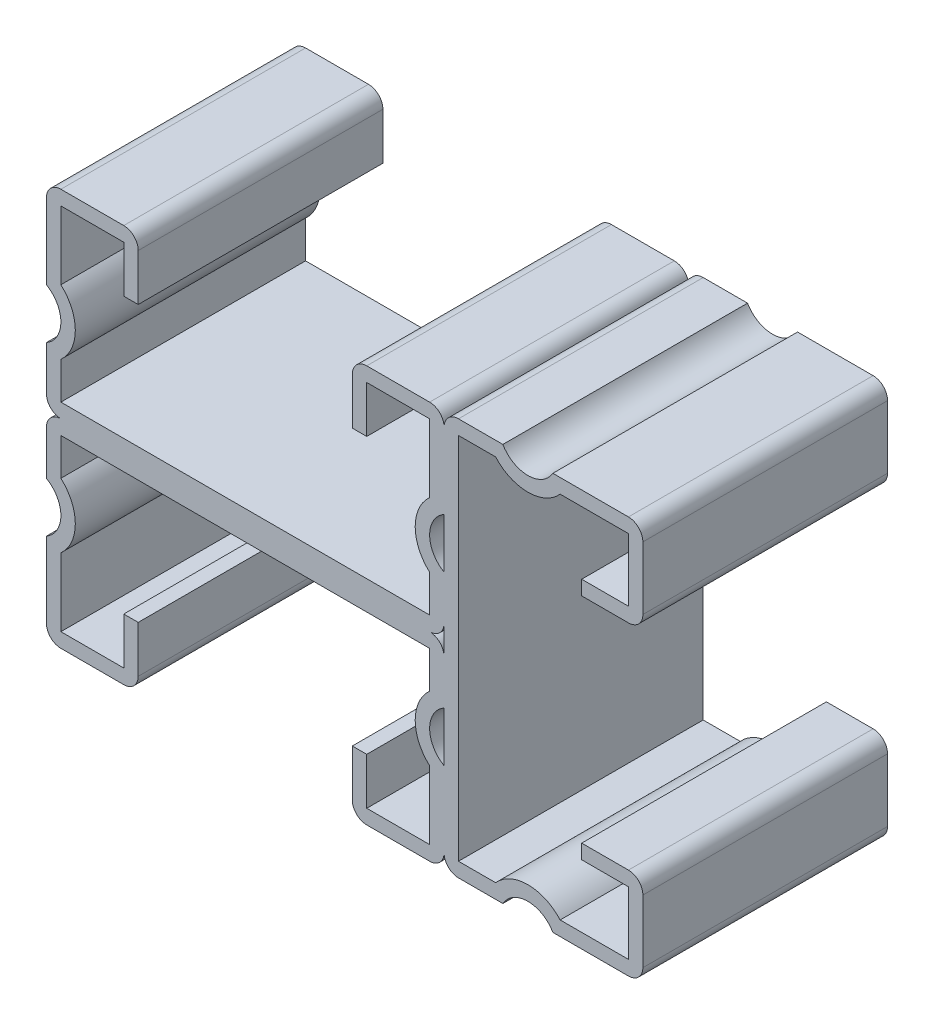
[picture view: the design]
ISO-10303-21;
HEADER;
FILE_DESCRIPTION(('STEP AP214'),'2;1');
FILE_NAME('part.step','',(''),(''),'','','');
FILE_SCHEMA(('AUTOMOTIVE_DESIGN { 1 0 10303 214 1 1 1 1 }'));
ENDSEC;
DATA;
#1=APPLICATION_CONTEXT('core data for automotive mechanical design processes');
#2=APPLICATION_PROTOCOL_DEFINITION('international standard','automotive_design',2000,#1);
#3=PRODUCT_CONTEXT('',#1,'mechanical');
#4=PRODUCT('Part','Part','',(#3));
#5=PRODUCT_RELATED_PRODUCT_CATEGORY('part','',(#4));
#6=PRODUCT_DEFINITION_FORMATION('','',#4);
#7=PRODUCT_DEFINITION_CONTEXT('part definition',#1,'design');
#8=PRODUCT_DEFINITION('design','',#6,#7);
#9=PRODUCT_DEFINITION_SHAPE('','',#8);
#10=(LENGTH_UNIT() NAMED_UNIT(*) SI_UNIT(.MILLI.,.METRE.));
#11=(NAMED_UNIT(*) PLANE_ANGLE_UNIT() SI_UNIT($,.RADIAN.));
#12=(NAMED_UNIT(*) SI_UNIT($,.STERADIAN.) SOLID_ANGLE_UNIT());
#13=UNCERTAINTY_MEASURE_WITH_UNIT(LENGTH_MEASURE(1.E-05),#10,'distance_accuracy_value','');
#14=(GEOMETRIC_REPRESENTATION_CONTEXT(3) GLOBAL_UNCERTAINTY_ASSIGNED_CONTEXT((#13)) GLOBAL_UNIT_ASSIGNED_CONTEXT((#10,
#11,#12)) REPRESENTATION_CONTEXT('',''));
#15=CARTESIAN_POINT('',(0.,0.,0.));
#16=DIRECTION('',(0.,0.,1.));
#17=DIRECTION('',(1.,0.,0.));
#18=AXIS2_PLACEMENT_3D('',#15,#16,#17);
#19=CARTESIAN_POINT('',(-19.1389,19.1389,12.7));
#20=DIRECTION('',(-1.,0.,0.));
#21=DIRECTION('',(0.,0.,1.));
#22=AXIS2_PLACEMENT_3D('',#19,#20,#21);
#23=PLANE('',#22);
#24=DIRECTION('',(0.,1.,0.));
#25=VECTOR('',#24,1.);
#26=CARTESIAN_POINT('',(-19.1389,19.1389,-12.7));
#27=LINE('',#26,#25);
#28=CARTESIAN_POINT('',(-19.1389,12.0504714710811,-12.7));
#29=VERTEX_POINT('',#28);
#30=CARTESIAN_POINT('',(-19.1389,19.1389,-12.7));
#31=VERTEX_POINT('',#30);
#32=EDGE_CURVE('E264',#29,#31,#27,.T.);
#33=ORIENTED_EDGE('',*,*,#32,.T.);
#34=DIRECTION('',(0.,0.,-1.));
#35=VECTOR('',#34,1.);
#36=CARTESIAN_POINT('',(-19.1389,19.1389,12.7));
#37=LINE('',#36,#35);
#38=CARTESIAN_POINT('',(-19.1389,19.1389,12.7));
#39=VERTEX_POINT('',#38);
#40=EDGE_CURVE('E11',#39,#31,#37,.T.);
#41=ORIENTED_EDGE('',*,*,#40,.F.);
#42=DIRECTION('',(0.,1.,0.));
#43=VECTOR('',#42,1.);
#44=CARTESIAN_POINT('',(-19.1389,19.1389,12.7));
#45=LINE('',#44,#43);
#46=CARTESIAN_POINT('',(-19.1389,12.0504714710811,12.7));
#47=VERTEX_POINT('',#46);
#48=EDGE_CURVE('E317',#47,#39,#45,.T.);
#49=ORIENTED_EDGE('',*,*,#48,.F.);
#50=DIRECTION('',(0.,0.,-1.));
#51=VECTOR('',#50,1.);
#52=CARTESIAN_POINT('',(-19.1389,12.0504714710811,12.7));
#53=LINE('',#52,#51);
#54=EDGE_CURVE('E260',#47,#29,#53,.T.);
#55=ORIENTED_EDGE('',*,*,#54,.T.);
#56=EDGE_LOOP('',(#33,#41,#49,#55));
#57=FACE_BOUND('',#56,.T.);
#58=ADVANCED_FACE('F39',(#57),#23,.F.);
#59=CARTESIAN_POINT('',(-19.1389,19.1389,12.7));
#60=DIRECTION('',(0.,1.,0.));
#61=DIRECTION('',(0.,0.,1.));
#62=AXIS2_PLACEMENT_3D('',#59,#60,#61);
#63=PLANE('',#62);
#64=DIRECTION('',(1.,0.,0.));
#65=VECTOR('',#64,1.);
#66=CARTESIAN_POINT('',(-19.1389,19.1389,-12.7));
#67=LINE('',#66,#65);
#68=CARTESIAN_POINT('',(-12.6111,19.1389,-12.7));
#69=VERTEX_POINT('',#68);
#70=EDGE_CURVE('E267',#31,#69,#67,.T.);
#71=ORIENTED_EDGE('',*,*,#70,.T.);
#72=DIRECTION('',(0.,0.,-1.));
#73=VECTOR('',#72,1.);
#74=CARTESIAN_POINT('',(-12.6111,19.1389,12.7));
#75=LINE('',#74,#73);
#76=CARTESIAN_POINT('',(-12.6111,19.1389,12.7));
#77=VERTEX_POINT('',#76);
#78=EDGE_CURVE('E47',#77,#69,#75,.T.);
#79=ORIENTED_EDGE('',*,*,#78,.F.);
#80=DIRECTION('',(1.,0.,0.));
#81=VECTOR('',#80,1.);
#82=CARTESIAN_POINT('',(-19.1389,19.1389,12.7));
#83=LINE('',#82,#81);
#84=EDGE_CURVE('E156',#39,#77,#83,.T.);
#85=ORIENTED_EDGE('',*,*,#84,.F.);
#86=ORIENTED_EDGE('',*,*,#40,.T.);
#87=EDGE_LOOP('',(#71,#79,#85,#86));
#88=FACE_BOUND('',#87,.T.);
#89=ADVANCED_FACE('F483',(#88),#63,.F.);
#90=CARTESIAN_POINT('',(-12.6111,19.1389,12.7));
#91=DIRECTION('',(1.,0.,0.));
#92=DIRECTION('',(0.,1.,0.));
#93=AXIS2_PLACEMENT_3D('',#90,#91,#92);
#94=PLANE('',#93);
#95=DIRECTION('',(0.,-1.,0.));
#96=VECTOR('',#95,1.);
#97=CARTESIAN_POINT('',(-12.6111,19.1389,-12.7));
#98=LINE('',#97,#96);
#99=CARTESIAN_POINT('',(-12.6111,14.2875,-12.7));
#100=VERTEX_POINT('',#99);
#101=EDGE_CURVE('E270',#69,#100,#98,.T.);
#102=ORIENTED_EDGE('',*,*,#101,.T.);
#103=DIRECTION('',(0.,0.,-1.));
#104=VECTOR('',#103,1.);
#105=CARTESIAN_POINT('',(-12.6111,14.2875,12.7));
#106=LINE('',#105,#104);
#107=CARTESIAN_POINT('',(-12.6111,14.2875,12.7));
#108=VERTEX_POINT('',#107);
#109=EDGE_CURVE('E390',#108,#100,#106,.T.);
#110=ORIENTED_EDGE('',*,*,#109,.F.);
#111=DIRECTION('',(0.,-1.,0.));
#112=VECTOR('',#111,1.);
#113=CARTESIAN_POINT('',(-12.6111,19.1389,12.7));
#114=LINE('',#113,#112);
#115=EDGE_CURVE('E398',#77,#108,#114,.T.);
#116=ORIENTED_EDGE('',*,*,#115,.F.);
#117=ORIENTED_EDGE('',*,*,#78,.T.);
#118=EDGE_LOOP('',(#102,#110,#116,#117));
#119=FACE_BOUND('',#118,.T.);
#120=ADVANCED_FACE('F396',(#119),#94,.F.);
#121=CARTESIAN_POINT('',(-12.6111,14.2875,12.7));
#122=DIRECTION('',(0.,1.,0.));
#123=DIRECTION('',(0.,0.,1.));
#124=AXIS2_PLACEMENT_3D('',#121,#122,#123);
#125=PLANE('',#124);
#126=DIRECTION('',(1.,0.,0.));
#127=VECTOR('',#126,1.);
#128=CARTESIAN_POINT('',(-12.6111,14.2875,-12.7));
#129=LINE('',#128,#127);
#130=CARTESIAN_POINT('',(-11.1125,14.2875,-12.7));
#131=VERTEX_POINT('',#130);
#132=EDGE_CURVE('E272',#100,#131,#129,.T.);
#133=ORIENTED_EDGE('',*,*,#132,.T.);
#134=DIRECTION('',(0.,0.,-1.));
#135=VECTOR('',#134,1.);
#136=CARTESIAN_POINT('',(-11.1125,14.2875,12.7));
#137=LINE('',#136,#135);
#138=CARTESIAN_POINT('',(-11.1125,14.2875,12.7));
#139=VERTEX_POINT('',#138);
#140=EDGE_CURVE('E387',#139,#131,#137,.T.);
#141=ORIENTED_EDGE('',*,*,#140,.F.);
#142=DIRECTION('',(1.,0.,0.));
#143=VECTOR('',#142,1.);
#144=CARTESIAN_POINT('',(-12.6111,14.2875,12.7));
#145=LINE('',#144,#143);
#146=EDGE_CURVE('E418',#108,#139,#145,.T.);
#147=ORIENTED_EDGE('',*,*,#146,.F.);
#148=ORIENTED_EDGE('',*,*,#109,.T.);
#149=EDGE_LOOP('',(#133,#141,#147,#148));
#150=FACE_BOUND('',#149,.T.);
#151=ADVANCED_FACE('F409',(#150),#125,.F.);
#152=CARTESIAN_POINT('',(-11.1125,19.1389,12.7));
#153=DIRECTION('',(-1.,0.,0.));
#154=DIRECTION('',(0.,-1.,0.));
#155=AXIS2_PLACEMENT_3D('',#152,#153,#154);
#156=PLANE('',#155);
#157=DIRECTION('',(0.,1.,0.));
#158=VECTOR('',#157,1.);
#159=CARTESIAN_POINT('',(-11.1125,19.1389,-12.7));
#160=LINE('',#159,#158);
#161=CARTESIAN_POINT('',(-11.1125,19.1389,-12.7));
#162=VERTEX_POINT('',#161);
#163=EDGE_CURVE('E274',#131,#162,#160,.T.);
#164=ORIENTED_EDGE('',*,*,#163,.T.);
#165=DIRECTION('',(0.,0.,-1.));
#166=VECTOR('',#165,1.);
#167=CARTESIAN_POINT('',(-11.1125,19.1389,12.7));
#168=LINE('',#167,#166);
#169=CARTESIAN_POINT('',(-11.1125,19.1389,12.7));
#170=VERTEX_POINT('',#169);
#171=EDGE_CURVE('E384',#170,#162,#168,.T.);
#172=ORIENTED_EDGE('',*,*,#171,.F.);
#173=DIRECTION('',(0.,1.,0.));
#174=VECTOR('',#173,1.);
#175=CARTESIAN_POINT('',(-11.1125,19.1389,12.7));
#176=LINE('',#175,#174);
#177=EDGE_CURVE('E415',#139,#170,#176,.T.);
#178=ORIENTED_EDGE('',*,*,#177,.F.);
#179=ORIENTED_EDGE('',*,*,#140,.T.);
#180=EDGE_LOOP('',(#164,#172,#178,#179));
#181=FACE_BOUND('',#180,.T.);
#182=ADVANCED_FACE('F413',(#181),#156,.F.);
#183=CARTESIAN_POINT('',(-12.6111,19.1389,12.7));
#184=DIRECTION('',(0.,0.,-1.));
#185=DIRECTION('',(-1.,0.,0.));
#186=AXIS2_PLACEMENT_3D('',#183,#184,#185);
#187=CYLINDRICAL_SURFACE('',#186,1.4986);
#188=CARTESIAN_POINT('',(-12.6111,19.1389,-12.7));
#189=DIRECTION('',(0.,0.,1.));
#190=DIRECTION('',(-1.,0.,0.));
#191=AXIS2_PLACEMENT_3D('',#188,#189,#190);
#192=CIRCLE('',#191,1.4986);
#193=CARTESIAN_POINT('',(-12.6111,20.6375,-12.7));
#194=VERTEX_POINT('',#193);
#195=EDGE_CURVE('E276',#162,#194,#192,.T.);
#196=ORIENTED_EDGE('',*,*,#195,.T.);
#197=DIRECTION('',(0.,0.,-1.));
#198=VECTOR('',#197,1.);
#199=CARTESIAN_POINT('',(-12.6111,20.6375,12.7));
#200=LINE('',#199,#198);
#201=CARTESIAN_POINT('',(-12.6111,20.6375,12.7));
#202=VERTEX_POINT('',#201);
#203=EDGE_CURVE('E381',#202,#194,#200,.T.);
#204=ORIENTED_EDGE('',*,*,#203,.F.);
#205=CARTESIAN_POINT('',(-12.6111,19.1389,12.7));
#206=DIRECTION('',(0.,0.,1.));
#207=DIRECTION('',(-1.,0.,0.));
#208=AXIS2_PLACEMENT_3D('',#205,#206,#207);
#209=CIRCLE('',#208,1.4986);
#210=EDGE_CURVE('E417',#170,#202,#209,.T.);
#211=ORIENTED_EDGE('',*,*,#210,.F.);
#212=ORIENTED_EDGE('',*,*,#171,.T.);
#213=EDGE_LOOP('',(#196,#204,#211,#212));
#214=FACE_BOUND('',#213,.T.);
#215=ADVANCED_FACE('F496',(#214),#187,.T.);
#216=CARTESIAN_POINT('',(-19.1389,20.6375,12.7));
#217=DIRECTION('',(0.,-1.,0.));
#218=DIRECTION('',(0.,0.,-1.));
#219=AXIS2_PLACEMENT_3D('',#216,#217,#218);
#220=PLANE('',#219);
#221=DIRECTION('',(-1.,0.,0.));
#222=VECTOR('',#221,1.);
#223=CARTESIAN_POINT('',(-19.1389,20.6375,-12.7));
#224=LINE('',#223,#222);
#225=CARTESIAN_POINT('',(-19.1389,20.6375,-12.7));
#226=VERTEX_POINT('',#225);
#227=EDGE_CURVE('E278',#194,#226,#224,.T.);
#228=ORIENTED_EDGE('',*,*,#227,.T.);
#229=DIRECTION('',(0.,0.,-1.));
#230=VECTOR('',#229,1.);
#231=CARTESIAN_POINT('',(-19.1389,20.6375,12.7));
#232=LINE('',#231,#230);
#233=CARTESIAN_POINT('',(-19.1389,20.6375,12.7));
#234=VERTEX_POINT('',#233);
#235=EDGE_CURVE('E378',#234,#226,#232,.T.);
#236=ORIENTED_EDGE('',*,*,#235,.F.);
#237=DIRECTION('',(-1.,0.,0.));
#238=VECTOR('',#237,1.);
#239=CARTESIAN_POINT('',(-19.1389,20.6375,12.7));
#240=LINE('',#239,#238);
#241=EDGE_CURVE('E420',#202,#234,#240,.T.);
#242=ORIENTED_EDGE('',*,*,#241,.F.);
#243=ORIENTED_EDGE('',*,*,#203,.T.);
#244=EDGE_LOOP('',(#228,#236,#242,#243));
#245=FACE_BOUND('',#244,.T.);
#246=ADVANCED_FACE('F499',(#245),#220,.F.);
#247=CARTESIAN_POINT('',(-19.1389,19.1389,12.7));
#248=DIRECTION('',(0.,0.,-1.));
#249=DIRECTION('',(-1.,0.,0.));
#250=AXIS2_PLACEMENT_3D('',#247,#248,#249);
#251=CYLINDRICAL_SURFACE('',#250,1.4986);
#252=CARTESIAN_POINT('',(-19.1389,19.1389,-12.7));
#253=DIRECTION('',(0.,0.,1.));
#254=DIRECTION('',(-1.,0.,0.));
#255=AXIS2_PLACEMENT_3D('',#252,#253,#254);
#256=CIRCLE('',#255,1.4986);
#257=CARTESIAN_POINT('',(-20.6375,19.1389,-12.7));
#258=VERTEX_POINT('',#257);
#259=EDGE_CURVE('E280',#226,#258,#256,.T.);
#260=ORIENTED_EDGE('',*,*,#259,.T.);
#261=DIRECTION('',(0.,0.,-1.));
#262=VECTOR('',#261,1.);
#263=CARTESIAN_POINT('',(-20.6375,19.1389,12.7));
#264=LINE('',#263,#262);
#265=CARTESIAN_POINT('',(-20.6375,19.1389,12.7));
#266=VERTEX_POINT('',#265);
#267=EDGE_CURVE('E375',#266,#258,#264,.T.);
#268=ORIENTED_EDGE('',*,*,#267,.F.);
#269=CARTESIAN_POINT('',(-19.1389,19.1389,12.7));
#270=DIRECTION('',(0.,0.,1.));
#271=DIRECTION('',(-1.,0.,0.));
#272=AXIS2_PLACEMENT_3D('',#269,#270,#271);
#273=CIRCLE('',#272,1.4986);
#274=EDGE_CURVE('E426',#234,#266,#273,.T.);
#275=ORIENTED_EDGE('',*,*,#274,.F.);
#276=ORIENTED_EDGE('',*,*,#235,.T.);
#277=EDGE_LOOP('',(#260,#268,#275,#276));
#278=FACE_BOUND('',#277,.T.);
#279=ADVANCED_FACE('F503',(#278),#251,.T.);
#280=CARTESIAN_POINT('',(-20.6375,19.1389,12.7));
#281=DIRECTION('',(1.,0.,0.));
#282=DIRECTION('',(0.,1.,0.));
#283=AXIS2_PLACEMENT_3D('',#280,#281,#282);
#284=PLANE('',#283);
#285=DIRECTION('',(0.,-1.,0.));
#286=VECTOR('',#285,1.);
#287=CARTESIAN_POINT('',(-20.6375,19.1389,-12.7));
#288=LINE('',#287,#286);
#289=CARTESIAN_POINT('',(-20.6375,11.2951513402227,-12.7));
#290=VERTEX_POINT('',#289);
#291=EDGE_CURVE('E282',#258,#290,#288,.T.);
#292=ORIENTED_EDGE('',*,*,#291,.T.);
#293=DIRECTION('',(0.,0.,-1.));
#294=VECTOR('',#293,1.);
#295=CARTESIAN_POINT('',(-20.6375,11.2951513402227,12.7));
#296=LINE('',#295,#294);
#297=CARTESIAN_POINT('',(-20.6375,11.2951513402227,12.7));
#298=VERTEX_POINT('',#297);
#299=EDGE_CURVE('E372',#298,#290,#296,.T.);
#300=ORIENTED_EDGE('',*,*,#299,.F.);
#301=DIRECTION('',(0.,-1.,0.));
#302=VECTOR('',#301,1.);
#303=CARTESIAN_POINT('',(-20.6375,19.1389,12.7));
#304=LINE('',#303,#302);
#305=EDGE_CURVE('E428',#266,#298,#304,.T.);
#306=ORIENTED_EDGE('',*,*,#305,.F.);
#307=ORIENTED_EDGE('',*,*,#267,.T.);
#308=EDGE_LOOP('',(#292,#300,#306,#307));
#309=FACE_BOUND('',#308,.T.);
#310=ADVANCED_FACE('F507',(#309),#284,.F.);
#311=CARTESIAN_POINT('',(-22.1361,8.69949999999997,12.7));
#312=DIRECTION('',(0.,0.,-1.));
#313=DIRECTION('',(-1.,0.,0.));
#314=AXIS2_PLACEMENT_3D('',#311,#312,#313);
#315=CYLINDRICAL_SURFACE('',#314,2.9972);
#316=CARTESIAN_POINT('',(-22.1361,8.69949999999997,-12.7));
#317=DIRECTION('',(0.,0.,-1.));
#318=DIRECTION('',(1.,0.,0.));
#319=AXIS2_PLACEMENT_3D('',#316,#317,#318);
#320=CIRCLE('',#319,2.9972);
#321=CARTESIAN_POINT('',(-20.6375,6.10384865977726,-12.7));
#322=VERTEX_POINT('',#321);
#323=EDGE_CURVE('E284',#290,#322,#320,.T.);
#324=ORIENTED_EDGE('',*,*,#323,.T.);
#325=DIRECTION('',(0.,0.,-1.));
#326=VECTOR('',#325,1.);
#327=CARTESIAN_POINT('',(-20.6375,6.10384865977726,12.7));
#328=LINE('',#327,#326);
#329=CARTESIAN_POINT('',(-20.6375,6.10384865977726,12.7));
#330=VERTEX_POINT('',#329);
#331=EDGE_CURVE('E369',#330,#322,#328,.T.);
#332=ORIENTED_EDGE('',*,*,#331,.F.);
#333=CARTESIAN_POINT('',(-22.1361,8.69949999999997,12.7));
#334=DIRECTION('',(0.,0.,-1.));
#335=DIRECTION('',(1.,0.,0.));
#336=AXIS2_PLACEMENT_3D('',#333,#334,#335);
#337=CIRCLE('',#336,2.9972);
#338=EDGE_CURVE('E430',#298,#330,#337,.T.);
#339=ORIENTED_EDGE('',*,*,#338,.F.);
#340=ORIENTED_EDGE('',*,*,#299,.T.);
#341=EDGE_LOOP('',(#324,#332,#339,#340));
#342=FACE_BOUND('',#341,.T.);
#343=ADVANCED_FACE('F511',(#342),#315,.F.);
#344=CARTESIAN_POINT('',(-20.6375,6.10384865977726,12.7));
#345=DIRECTION('',(1.,0.,0.));
#346=DIRECTION('',(0.,0.,-1.));
#347=AXIS2_PLACEMENT_3D('',#344,#345,#346);
#348=PLANE('',#347);
#349=DIRECTION('',(0.,-1.,0.));
#350=VECTOR('',#349,1.);
#351=CARTESIAN_POINT('',(-20.6375,6.10384865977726,-12.7));
#352=LINE('',#351,#350);
#353=CARTESIAN_POINT('',(-20.6375,1.4986,-12.7));
#354=VERTEX_POINT('',#353);
#355=EDGE_CURVE('E286',#322,#354,#352,.T.);
#356=ORIENTED_EDGE('',*,*,#355,.T.);
#357=DIRECTION('',(0.,0.,-1.));
#358=VECTOR('',#357,1.);
#359=CARTESIAN_POINT('',(-20.6375,1.4986,12.7));
#360=LINE('',#359,#358);
#361=CARTESIAN_POINT('',(-20.6375,1.4986,12.7));
#362=VERTEX_POINT('',#361);
#363=EDGE_CURVE('E366',#362,#354,#360,.T.);
#364=ORIENTED_EDGE('',*,*,#363,.F.);
#365=DIRECTION('',(0.,-1.,0.));
#366=VECTOR('',#365,1.);
#367=CARTESIAN_POINT('',(-20.6375,6.10384865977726,12.7));
#368=LINE('',#367,#366);
#369=EDGE_CURVE('E432',#330,#362,#368,.T.);
#370=ORIENTED_EDGE('',*,*,#369,.F.);
#371=ORIENTED_EDGE('',*,*,#331,.T.);
#372=EDGE_LOOP('',(#356,#364,#370,#371));
#373=FACE_BOUND('',#372,.T.);
#374=ADVANCED_FACE('F515',(#373),#348,.F.);
#375=CARTESIAN_POINT('',(-19.1389,1.4986,12.7));
#376=DIRECTION('',(0.,0.,-1.));
#377=DIRECTION('',(-1.,0.,0.));
#378=AXIS2_PLACEMENT_3D('',#375,#376,#377);
#379=CYLINDRICAL_SURFACE('',#378,1.4986);
#380=CARTESIAN_POINT('',(-19.1389,1.4986,-12.7));
#381=DIRECTION('',(0.,0.,1.));
#382=DIRECTION('',(-1.,0.,0.));
#383=AXIS2_PLACEMENT_3D('',#380,#381,#382);
#384=CIRCLE('',#383,1.4986);
#385=CARTESIAN_POINT('',(-19.1389,0.,-12.7));
#386=VERTEX_POINT('',#385);
#387=EDGE_CURVE('E288',#354,#386,#384,.T.);
#388=ORIENTED_EDGE('',*,*,#387,.T.);
#389=DIRECTION('',(0.,0.,-1.));
#390=VECTOR('',#389,1.);
#391=CARTESIAN_POINT('',(-19.1389,0.,12.7));
#392=LINE('',#391,#390);
#393=CARTESIAN_POINT('',(-19.1389,0.,12.7));
#394=VERTEX_POINT('',#393);
#395=EDGE_CURVE('E363',#394,#386,#392,.T.);
#396=ORIENTED_EDGE('',*,*,#395,.F.);
#397=CARTESIAN_POINT('',(-19.1389,1.4986,12.7));
#398=DIRECTION('',(0.,0.,1.));
#399=DIRECTION('',(-1.,0.,0.));
#400=AXIS2_PLACEMENT_3D('',#397,#398,#399);
#401=CIRCLE('',#400,1.4986);
#402=EDGE_CURVE('E434',#362,#394,#401,.T.);
#403=ORIENTED_EDGE('',*,*,#402,.F.);
#404=ORIENTED_EDGE('',*,*,#363,.T.);
#405=EDGE_LOOP('',(#388,#396,#403,#404));
#406=FACE_BOUND('',#405,.T.);
#407=ADVANCED_FACE('F519',(#406),#379,.T.);
#408=CARTESIAN_POINT('',(19.1389,1.49860000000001,12.7));
#409=DIRECTION('',(0.,0.,-1.));
#410=DIRECTION('',(-1.,0.,0.));
#411=AXIS2_PLACEMENT_3D('',#408,#409,#410);
#412=CYLINDRICAL_SURFACE('',#411,1.4986);
#413=CARTESIAN_POINT('',(19.1389,1.49860000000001,-12.7));
#414=DIRECTION('',(0.,0.,1.));
#415=DIRECTION('',(-1.,0.,0.));
#416=AXIS2_PLACEMENT_3D('',#413,#414,#415);
#417=CIRCLE('',#416,1.4986);
#418=CARTESIAN_POINT('',(19.1389,0.,-12.7));
#419=VERTEX_POINT('',#418);
#420=CARTESIAN_POINT('',(20.6375,1.49860000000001,-12.7));
#421=VERTEX_POINT('',#420);
#422=EDGE_CURVE('E290',#419,#421,#417,.T.);
#423=ORIENTED_EDGE('',*,*,#422,.T.);
#424=DIRECTION('',(0.,0.,-1.));
#425=VECTOR('',#424,1.);
#426=CARTESIAN_POINT('',(20.6375,1.49860000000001,12.7));
#427=LINE('',#426,#425);
#428=CARTESIAN_POINT('',(20.6375,1.49860000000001,12.7));
#429=VERTEX_POINT('',#428);
#430=EDGE_CURVE('E357',#429,#421,#427,.T.);
#431=ORIENTED_EDGE('',*,*,#430,.F.);
#432=CARTESIAN_POINT('',(19.1389,1.49860000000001,12.7));
#433=DIRECTION('',(0.,0.,1.));
#434=DIRECTION('',(-1.,0.,0.));
#435=AXIS2_PLACEMENT_3D('',#432,#433,#434);
#436=CIRCLE('',#435,1.4986);
#437=CARTESIAN_POINT('',(19.1389,0.,12.7));
#438=VERTEX_POINT('',#437);
#439=EDGE_CURVE('E436',#438,#429,#436,.T.);
#440=ORIENTED_EDGE('',*,*,#439,.F.);
#441=DIRECTION('',(0.,0.,-1.));
#442=VECTOR('',#441,1.);
#443=CARTESIAN_POINT('',(19.1389,0.,12.7));
#444=LINE('',#443,#442);
#445=EDGE_CURVE('E360',#438,#419,#444,.T.);
#446=ORIENTED_EDGE('',*,*,#445,.T.);
#447=EDGE_LOOP('',(#423,#431,#440,#446));
#448=FACE_BOUND('',#447,.T.);
#449=ADVANCED_FACE('F522',(#448),#412,.T.);
#450=CARTESIAN_POINT('',(22.1361,8.69949999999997,12.7));
#451=DIRECTION('',(0.,0.,-1.));
#452=DIRECTION('',(-1.,0.,0.));
#453=AXIS2_PLACEMENT_3D('',#450,#451,#452);
#454=CYLINDRICAL_SURFACE('',#453,2.9972);
#455=CARTESIAN_POINT('',(22.1361,8.69949999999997,-12.7));
#456=DIRECTION('',(0.,0.,-1.));
#457=DIRECTION('',(1.,0.,0.));
#458=AXIS2_PLACEMENT_3D('',#455,#456,#457);
#459=CIRCLE('',#458,2.9972);
#460=CARTESIAN_POINT('',(20.6375,6.10384865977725,-12.7));
#461=VERTEX_POINT('',#460);
#462=CARTESIAN_POINT('',(20.6375,11.2951513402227,-12.7));
#463=VERTEX_POINT('',#462);
#464=EDGE_CURVE('E292',#461,#463,#459,.T.);
#465=ORIENTED_EDGE('',*,*,#464,.T.);
#466=DIRECTION('',(0.,0.,-1.));
#467=VECTOR('',#466,1.);
#468=CARTESIAN_POINT('',(20.6375,11.2951513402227,12.7));
#469=LINE('',#468,#467);
#470=CARTESIAN_POINT('',(20.6375,11.2951513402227,12.7));
#471=VERTEX_POINT('',#470);
#472=EDGE_CURVE('E351',#471,#463,#469,.T.);
#473=ORIENTED_EDGE('',*,*,#472,.F.);
#474=CARTESIAN_POINT('',(22.1361,8.69949999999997,12.7));
#475=DIRECTION('',(0.,0.,-1.));
#476=DIRECTION('',(1.,0.,0.));
#477=AXIS2_PLACEMENT_3D('',#474,#475,#476);
#478=CIRCLE('',#477,2.9972);
#479=CARTESIAN_POINT('',(20.6375,6.10384865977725,12.7));
#480=VERTEX_POINT('',#479);
#481=EDGE_CURVE('E438',#480,#471,#478,.T.);
#482=ORIENTED_EDGE('',*,*,#481,.F.);
#483=DIRECTION('',(0.,0.,-1.));
#484=VECTOR('',#483,1.);
#485=CARTESIAN_POINT('',(20.6375,6.10384865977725,12.7));
#486=LINE('',#485,#484);
#487=EDGE_CURVE('E354',#480,#461,#486,.T.);
#488=ORIENTED_EDGE('',*,*,#487,.T.);
#489=EDGE_LOOP('',(#465,#473,#482,#488));
#490=FACE_BOUND('',#489,.T.);
#491=ADVANCED_FACE('F526',(#490),#454,.F.);
#492=CARTESIAN_POINT('',(19.1389,19.1389,12.7));
#493=DIRECTION('',(0.,0.,-1.));
#494=DIRECTION('',(-1.,0.,0.));
#495=AXIS2_PLACEMENT_3D('',#492,#493,#494);
#496=CYLINDRICAL_SURFACE('',#495,1.4986);
#497=CARTESIAN_POINT('',(19.1389,19.1389,-12.7));
#498=DIRECTION('',(0.,0.,1.));
#499=DIRECTION('',(-1.,0.,0.));
#500=AXIS2_PLACEMENT_3D('',#497,#498,#499);
#501=CIRCLE('',#500,1.4986);
#502=CARTESIAN_POINT('',(20.6375,19.1389,-12.7));
#503=VERTEX_POINT('',#502);
#504=CARTESIAN_POINT('',(19.1389,20.6375,-12.7));
#505=VERTEX_POINT('',#504);
#506=EDGE_CURVE('E294',#503,#505,#501,.T.);
#507=ORIENTED_EDGE('',*,*,#506,.T.);
#508=DIRECTION('',(0.,0.,-1.));
#509=VECTOR('',#508,1.);
#510=CARTESIAN_POINT('',(19.1389,20.6375,12.7));
#511=LINE('',#510,#509);
#512=CARTESIAN_POINT('',(19.1389,20.6375,12.7));
#513=VERTEX_POINT('',#512);
#514=EDGE_CURVE('E345',#513,#505,#511,.T.);
#515=ORIENTED_EDGE('',*,*,#514,.F.);
#516=CARTESIAN_POINT('',(19.1389,19.1389,12.7));
#517=DIRECTION('',(0.,0.,1.));
#518=DIRECTION('',(-1.,0.,0.));
#519=AXIS2_PLACEMENT_3D('',#516,#517,#518);
#520=CIRCLE('',#519,1.4986);
#521=CARTESIAN_POINT('',(20.6375,19.1389,12.7));
#522=VERTEX_POINT('',#521);
#523=EDGE_CURVE('E440',#522,#513,#520,.T.);
#524=ORIENTED_EDGE('',*,*,#523,.F.);
#525=DIRECTION('',(0.,0.,-1.));
#526=VECTOR('',#525,1.);
#527=CARTESIAN_POINT('',(20.6375,19.1389,12.7));
#528=LINE('',#527,#526);
#529=EDGE_CURVE('E348',#522,#503,#528,.T.);
#530=ORIENTED_EDGE('',*,*,#529,.T.);
#531=EDGE_LOOP('',(#507,#515,#524,#530));
#532=FACE_BOUND('',#531,.T.);
#533=ADVANCED_FACE('F530',(#532),#496,.T.);
#534=CARTESIAN_POINT('',(19.1389,20.6375,12.7));
#535=DIRECTION('',(0.,-1.,0.));
#536=DIRECTION('',(1.,0.,0.));
#537=AXIS2_PLACEMENT_3D('',#534,#535,#536);
#538=PLANE('',#537);
#539=DIRECTION('',(-1.,0.,0.));
#540=VECTOR('',#539,1.);
#541=CARTESIAN_POINT('',(19.1389,20.6375,-12.7));
#542=LINE('',#541,#540);
#543=CARTESIAN_POINT('',(12.6111,20.6375,-12.7));
#544=VERTEX_POINT('',#543);
#545=EDGE_CURVE('E296',#505,#544,#542,.T.);
#546=ORIENTED_EDGE('',*,*,#545,.T.);
#547=DIRECTION('',(0.,0.,-1.));
#548=VECTOR('',#547,1.);
#549=CARTESIAN_POINT('',(12.6111,20.6375,12.7));
#550=LINE('',#549,#548);
#551=CARTESIAN_POINT('',(12.6111,20.6375,12.7));
#552=VERTEX_POINT('',#551);
#553=EDGE_CURVE('E342',#552,#544,#550,.T.);
#554=ORIENTED_EDGE('',*,*,#553,.F.);
#555=DIRECTION('',(-1.,0.,0.));
#556=VECTOR('',#555,1.);
#557=CARTESIAN_POINT('',(19.1389,20.6375,12.7));
#558=LINE('',#557,#556);
#559=EDGE_CURVE('E442',#513,#552,#558,.T.);
#560=ORIENTED_EDGE('',*,*,#559,.F.);
#561=ORIENTED_EDGE('',*,*,#514,.T.);
#562=EDGE_LOOP('',(#546,#554,#560,#561));
#563=FACE_BOUND('',#562,.T.);
#564=ADVANCED_FACE('F534',(#563),#538,.F.);
#565=CARTESIAN_POINT('',(12.6111,19.1389,12.7));
#566=DIRECTION('',(0.,0.,-1.));
#567=DIRECTION('',(-1.,0.,0.));
#568=AXIS2_PLACEMENT_3D('',#565,#566,#567);
#569=CYLINDRICAL_SURFACE('',#568,1.4986);
#570=CARTESIAN_POINT('',(12.6111,19.1389,-12.7));
#571=DIRECTION('',(0.,0.,1.));
#572=DIRECTION('',(-1.,0.,0.));
#573=AXIS2_PLACEMENT_3D('',#570,#571,#572);
#574=CIRCLE('',#573,1.4986);
#575=CARTESIAN_POINT('',(11.1125,19.1389,-12.7));
#576=VERTEX_POINT('',#575);
#577=EDGE_CURVE('E298',#544,#576,#574,.T.);
#578=ORIENTED_EDGE('',*,*,#577,.T.);
#579=DIRECTION('',(0.,0.,-1.));
#580=VECTOR('',#579,1.);
#581=CARTESIAN_POINT('',(11.1125,19.1389,12.7));
#582=LINE('',#581,#580);
#583=CARTESIAN_POINT('',(11.1125,19.1389,12.7));
#584=VERTEX_POINT('',#583);
#585=EDGE_CURVE('E339',#584,#576,#582,.T.);
#586=ORIENTED_EDGE('',*,*,#585,.F.);
#587=CARTESIAN_POINT('',(12.6111,19.1389,12.7));
#588=DIRECTION('',(0.,0.,1.));
#589=DIRECTION('',(-1.,0.,0.));
#590=AXIS2_PLACEMENT_3D('',#587,#588,#589);
#591=CIRCLE('',#590,1.4986);
#592=EDGE_CURVE('E444',#552,#584,#591,.T.);
#593=ORIENTED_EDGE('',*,*,#592,.F.);
#594=ORIENTED_EDGE('',*,*,#553,.T.);
#595=EDGE_LOOP('',(#578,#586,#593,#594));
#596=FACE_BOUND('',#595,.T.);
#597=ADVANCED_FACE('F538',(#596),#569,.T.);
#598=CARTESIAN_POINT('',(11.1125,19.1389,12.7));
#599=DIRECTION('',(1.,0.,0.));
#600=DIRECTION('',(0.,1.,0.));
#601=AXIS2_PLACEMENT_3D('',#598,#599,#600);
#602=PLANE('',#601);
#603=DIRECTION('',(0.,-1.,0.));
#604=VECTOR('',#603,1.);
#605=CARTESIAN_POINT('',(11.1125,19.1389,-12.7));
#606=LINE('',#605,#604);
#607=CARTESIAN_POINT('',(11.1125,14.2875,-12.7));
#608=VERTEX_POINT('',#607);
#609=EDGE_CURVE('E300',#576,#608,#606,.T.);
#610=ORIENTED_EDGE('',*,*,#609,.T.);
#611=DIRECTION('',(0.,0.,-1.));
#612=VECTOR('',#611,1.);
#613=CARTESIAN_POINT('',(11.1125,14.2875,12.7));
#614=LINE('',#613,#612);
#615=CARTESIAN_POINT('',(11.1125,14.2875,12.7));
#616=VERTEX_POINT('',#615);
#617=EDGE_CURVE('E336',#616,#608,#614,.T.);
#618=ORIENTED_EDGE('',*,*,#617,.F.);
#619=DIRECTION('',(0.,-1.,0.));
#620=VECTOR('',#619,1.);
#621=CARTESIAN_POINT('',(11.1125,19.1389,12.7));
#622=LINE('',#621,#620);
#623=EDGE_CURVE('E446',#584,#616,#622,.T.);
#624=ORIENTED_EDGE('',*,*,#623,.F.);
#625=ORIENTED_EDGE('',*,*,#585,.T.);
#626=EDGE_LOOP('',(#610,#618,#624,#625));
#627=FACE_BOUND('',#626,.T.);
#628=ADVANCED_FACE('F542',(#627),#602,.F.);
#629=CARTESIAN_POINT('',(11.1125,14.2875,12.7));
#630=DIRECTION('',(0.,1.,0.));
#631=DIRECTION('',(0.,0.,1.));
#632=AXIS2_PLACEMENT_3D('',#629,#630,#631);
#633=PLANE('',#632);
#634=DIRECTION('',(1.,0.,0.));
#635=VECTOR('',#634,1.);
#636=CARTESIAN_POINT('',(11.1125,14.2875,-12.7));
#637=LINE('',#636,#635);
#638=CARTESIAN_POINT('',(12.6111,14.2875,-12.7));
#639=VERTEX_POINT('',#638);
#640=EDGE_CURVE('E302',#608,#639,#637,.T.);
#641=ORIENTED_EDGE('',*,*,#640,.T.);
#642=DIRECTION('',(0.,0.,-1.));
#643=VECTOR('',#642,1.);
#644=CARTESIAN_POINT('',(12.6111,14.2875,12.7));
#645=LINE('',#644,#643);
#646=CARTESIAN_POINT('',(12.6111,14.2875,12.7));
#647=VERTEX_POINT('',#646);
#648=EDGE_CURVE('E333',#647,#639,#645,.T.);
#649=ORIENTED_EDGE('',*,*,#648,.F.);
#650=DIRECTION('',(1.,0.,0.));
#651=VECTOR('',#650,1.);
#652=CARTESIAN_POINT('',(11.1125,14.2875,12.7));
#653=LINE('',#652,#651);
#654=EDGE_CURVE('E448',#616,#647,#653,.T.);
#655=ORIENTED_EDGE('',*,*,#654,.F.);
#656=ORIENTED_EDGE('',*,*,#617,.T.);
#657=EDGE_LOOP('',(#641,#649,#655,#656));
#658=FACE_BOUND('',#657,.T.);
#659=ADVANCED_FACE('F546',(#658),#633,.F.);
#660=CARTESIAN_POINT('',(12.6111,19.1389,12.7));
#661=DIRECTION('',(-1.,0.,0.));
#662=DIRECTION('',(0.,0.,1.));
#663=AXIS2_PLACEMENT_3D('',#660,#661,#662);
#664=PLANE('',#663);
#665=DIRECTION('',(0.,1.,0.));
#666=VECTOR('',#665,1.);
#667=CARTESIAN_POINT('',(12.6111,19.1389,-12.7));
#668=LINE('',#667,#666);
#669=CARTESIAN_POINT('',(12.6111,19.1389,-12.7));
#670=VERTEX_POINT('',#669);
#671=EDGE_CURVE('E304',#639,#670,#668,.T.);
#672=ORIENTED_EDGE('',*,*,#671,.T.);
#673=DIRECTION('',(0.,0.,-1.));
#674=VECTOR('',#673,1.);
#675=CARTESIAN_POINT('',(12.6111,19.1389,12.7));
#676=LINE('',#675,#674);
#677=CARTESIAN_POINT('',(12.6111,19.1389,12.7));
#678=VERTEX_POINT('',#677);
#679=EDGE_CURVE('E330',#678,#670,#676,.T.);
#680=ORIENTED_EDGE('',*,*,#679,.F.);
#681=DIRECTION('',(0.,1.,0.));
#682=VECTOR('',#681,1.);
#683=CARTESIAN_POINT('',(12.6111,19.1389,12.7));
#684=LINE('',#683,#682);
#685=EDGE_CURVE('E450',#647,#678,#684,.T.);
#686=ORIENTED_EDGE('',*,*,#685,.F.);
#687=ORIENTED_EDGE('',*,*,#648,.T.);
#688=EDGE_LOOP('',(#672,#680,#686,#687));
#689=FACE_BOUND('',#688,.T.);
#690=ADVANCED_FACE('F550',(#689),#664,.F.);
#691=CARTESIAN_POINT('',(19.1389,19.1389,12.7));
#692=DIRECTION('',(0.,1.,0.));
#693=DIRECTION('',(-1.,0.,0.));
#694=AXIS2_PLACEMENT_3D('',#691,#692,#693);
#695=PLANE('',#694);
#696=DIRECTION('',(1.,0.,0.));
#697=VECTOR('',#696,1.);
#698=CARTESIAN_POINT('',(19.1389,19.1389,-12.7));
#699=LINE('',#698,#697);
#700=CARTESIAN_POINT('',(19.1389,19.1389,-12.7));
#701=VERTEX_POINT('',#700);
#702=EDGE_CURVE('E306',#670,#701,#699,.T.);
#703=ORIENTED_EDGE('',*,*,#702,.T.);
#704=DIRECTION('',(0.,0.,-1.));
#705=VECTOR('',#704,1.);
#706=CARTESIAN_POINT('',(19.1389,19.1389,12.7));
#707=LINE('',#706,#705);
#708=CARTESIAN_POINT('',(19.1389,19.1389,12.7));
#709=VERTEX_POINT('',#708);
#710=EDGE_CURVE('E327',#709,#701,#707,.T.);
#711=ORIENTED_EDGE('',*,*,#710,.F.);
#712=DIRECTION('',(1.,0.,0.));
#713=VECTOR('',#712,1.);
#714=CARTESIAN_POINT('',(19.1389,19.1389,12.7));
#715=LINE('',#714,#713);
#716=EDGE_CURVE('E452',#678,#709,#715,.T.);
#717=ORIENTED_EDGE('',*,*,#716,.F.);
#718=ORIENTED_EDGE('',*,*,#679,.T.);
#719=EDGE_LOOP('',(#703,#711,#717,#718));
#720=FACE_BOUND('',#719,.T.);
#721=ADVANCED_FACE('F554',(#720),#695,.F.);
#722=CARTESIAN_POINT('',(19.1389,12.0504714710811,12.7));
#723=DIRECTION('',(1.,0.,0.));
#724=DIRECTION('',(0.,0.,-1.));
#725=AXIS2_PLACEMENT_3D('',#722,#723,#724);
#726=PLANE('',#725);
#727=DIRECTION('',(0.,-1.,0.));
#728=VECTOR('',#727,1.);
#729=CARTESIAN_POINT('',(19.1389,12.0504714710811,-12.7));
#730=LINE('',#729,#728);
#731=CARTESIAN_POINT('',(19.1389,12.0504714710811,-12.7));
#732=VERTEX_POINT('',#731);
#733=EDGE_CURVE('E308',#701,#732,#730,.T.);
#734=ORIENTED_EDGE('',*,*,#733,.T.);
#735=DIRECTION('',(0.,0.,-1.));
#736=VECTOR('',#735,1.);
#737=CARTESIAN_POINT('',(19.1389,12.0504714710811,12.7));
#738=LINE('',#737,#736);
#739=CARTESIAN_POINT('',(19.1389,12.0504714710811,12.7));
#740=VERTEX_POINT('',#739);
#741=EDGE_CURVE('E324',#740,#732,#738,.T.);
#742=ORIENTED_EDGE('',*,*,#741,.F.);
#743=DIRECTION('',(0.,-1.,0.));
#744=VECTOR('',#743,1.);
#745=CARTESIAN_POINT('',(19.1389,12.0504714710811,12.7));
#746=LINE('',#745,#744);
#747=EDGE_CURVE('E454',#709,#740,#746,.T.);
#748=ORIENTED_EDGE('',*,*,#747,.F.);
#749=ORIENTED_EDGE('',*,*,#710,.T.);
#750=EDGE_LOOP('',(#734,#742,#748,#749));
#751=FACE_BOUND('',#750,.T.);
#752=ADVANCED_FACE('F558',(#751),#726,.F.);
#753=CARTESIAN_POINT('',(22.1361,8.69949999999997,12.7));
#754=DIRECTION('',(0.,0.,-1.));
#755=DIRECTION('',(-1.,0.,0.));
#756=AXIS2_PLACEMENT_3D('',#753,#754,#755);
#757=CYLINDRICAL_SURFACE('',#756,4.4958);
#758=CARTESIAN_POINT('',(22.1361,8.69949999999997,-12.7));
#759=DIRECTION('',(0.,0.,1.));
#760=DIRECTION('',(1.,0.,0.));
#761=AXIS2_PLACEMENT_3D('',#758,#759,#760);
#762=CIRCLE('',#761,4.4958);
#763=CARTESIAN_POINT('',(19.1389,5.34852852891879,-12.7));
#764=VERTEX_POINT('',#763);
#765=EDGE_CURVE('E310',#732,#764,#762,.T.);
#766=ORIENTED_EDGE('',*,*,#765,.T.);
#767=DIRECTION('',(0.,0.,-1.));
#768=VECTOR('',#767,1.);
#769=CARTESIAN_POINT('',(19.1389,5.34852852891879,12.7));
#770=LINE('',#769,#768);
#771=CARTESIAN_POINT('',(19.1389,5.34852852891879,12.7));
#772=VERTEX_POINT('',#771);
#773=EDGE_CURVE('E321',#772,#764,#770,.T.);
#774=ORIENTED_EDGE('',*,*,#773,.F.);
#775=CARTESIAN_POINT('',(22.1361,8.69949999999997,12.7));
#776=DIRECTION('',(0.,0.,1.));
#777=DIRECTION('',(1.,0.,0.));
#778=AXIS2_PLACEMENT_3D('',#775,#776,#777);
#779=CIRCLE('',#778,4.4958);
#780=EDGE_CURVE('E456',#740,#772,#779,.T.);
#781=ORIENTED_EDGE('',*,*,#780,.F.);
#782=ORIENTED_EDGE('',*,*,#741,.T.);
#783=EDGE_LOOP('',(#766,#774,#781,#782));
#784=FACE_BOUND('',#783,.T.);
#785=ADVANCED_FACE('F462',(#784),#757,.T.);
#786=CARTESIAN_POINT('',(19.1389,1.49860000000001,12.7));
#787=DIRECTION('',(1.,0.,0.));
#788=DIRECTION('',(0.,0.,-1.));
#789=AXIS2_PLACEMENT_3D('',#786,#787,#788);
#790=PLANE('',#789);
#791=DIRECTION('',(0.,-1.,0.));
#792=VECTOR('',#791,1.);
#793=CARTESIAN_POINT('',(19.1389,1.49860000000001,-12.7));
#794=LINE('',#793,#792);
#795=CARTESIAN_POINT('',(19.1389,1.49860000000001,-12.7));
#796=VERTEX_POINT('',#795);
#797=EDGE_CURVE('E312',#764,#796,#794,.T.);
#798=ORIENTED_EDGE('',*,*,#797,.T.);
#799=DIRECTION('',(0.,0.,-1.));
#800=VECTOR('',#799,1.);
#801=CARTESIAN_POINT('',(19.1389,1.49860000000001,12.7));
#802=LINE('',#801,#800);
#803=CARTESIAN_POINT('',(19.1389,1.49860000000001,12.7));
#804=VERTEX_POINT('',#803);
#805=EDGE_CURVE('E255',#804,#796,#802,.T.);
#806=ORIENTED_EDGE('',*,*,#805,.F.);
#807=DIRECTION('',(0.,-1.,0.));
#808=VECTOR('',#807,1.);
#809=CARTESIAN_POINT('',(19.1389,1.49860000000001,12.7));
#810=LINE('',#809,#808);
#811=EDGE_CURVE('E246',#772,#804,#810,.T.);
#812=ORIENTED_EDGE('',*,*,#811,.F.);
#813=ORIENTED_EDGE('',*,*,#773,.T.);
#814=EDGE_LOOP('',(#798,#806,#812,#813));
#815=FACE_BOUND('',#814,.T.);
#816=ADVANCED_FACE('F466',(#815),#790,.F.);
#817=CARTESIAN_POINT('',(-19.1389,1.4986,12.7));
#818=DIRECTION('',(0.,-1.,0.));
#819=DIRECTION('',(1.,0.,0.));
#820=AXIS2_PLACEMENT_3D('',#817,#818,#819);
#821=PLANE('',#820);
#822=DIRECTION('',(-1.,0.,0.));
#823=VECTOR('',#822,1.);
#824=CARTESIAN_POINT('',(-19.1389,1.4986,-12.7));
#825=LINE('',#824,#823);
#826=CARTESIAN_POINT('',(-19.1389,1.4986,-12.7));
#827=VERTEX_POINT('',#826);
#828=EDGE_CURVE('E254',#796,#827,#825,.T.);
#829=ORIENTED_EDGE('',*,*,#828,.T.);
#830=DIRECTION('',(0.,0.,-1.));
#831=VECTOR('',#830,1.);
#832=CARTESIAN_POINT('',(-19.1389,1.4986,12.7));
#833=LINE('',#832,#831);
#834=CARTESIAN_POINT('',(-19.1389,1.4986,12.7));
#835=VERTEX_POINT('',#834);
#836=EDGE_CURVE('E251',#835,#827,#833,.T.);
#837=ORIENTED_EDGE('',*,*,#836,.F.);
#838=DIRECTION('',(-1.,0.,0.));
#839=VECTOR('',#838,1.);
#840=CARTESIAN_POINT('',(-19.1389,1.4986,12.7));
#841=LINE('',#840,#839);
#842=EDGE_CURVE('E238',#804,#835,#841,.T.);
#843=ORIENTED_EDGE('',*,*,#842,.F.);
#844=ORIENTED_EDGE('',*,*,#805,.T.);
#845=EDGE_LOOP('',(#829,#837,#843,#844));
#846=FACE_BOUND('',#845,.T.);
#847=ADVANCED_FACE('F252',(#846),#821,.F.);
#848=CARTESIAN_POINT('',(-19.1389,5.34852852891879,12.7));
#849=DIRECTION('',(-1.,0.,0.));
#850=DIRECTION('',(0.,-1.,0.));
#851=AXIS2_PLACEMENT_3D('',#848,#849,#850);
#852=PLANE('',#851);
#853=DIRECTION('',(0.,1.,0.));
#854=VECTOR('',#853,1.);
#855=CARTESIAN_POINT('',(-19.1389,5.34852852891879,-12.7));
#856=LINE('',#855,#854);
#857=CARTESIAN_POINT('',(-19.1389,5.34852852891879,-12.7));
#858=VERTEX_POINT('',#857);
#859=EDGE_CURVE('E142',#827,#858,#856,.T.);
#860=ORIENTED_EDGE('',*,*,#859,.T.);
#861=DIRECTION('',(0.,0.,-1.));
#862=VECTOR('',#861,1.);
#863=CARTESIAN_POINT('',(-19.1389,5.34852852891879,12.7));
#864=LINE('',#863,#862);
#865=CARTESIAN_POINT('',(-19.1389,5.34852852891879,12.7));
#866=VERTEX_POINT('',#865);
#867=EDGE_CURVE('E256',#866,#858,#864,.T.);
#868=ORIENTED_EDGE('',*,*,#867,.F.);
#869=DIRECTION('',(0.,1.,0.));
#870=VECTOR('',#869,1.);
#871=CARTESIAN_POINT('',(-19.1389,5.34852852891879,12.7));
#872=LINE('',#871,#870);
#873=EDGE_CURVE('E244',#835,#866,#872,.T.);
#874=ORIENTED_EDGE('',*,*,#873,.F.);
#875=ORIENTED_EDGE('',*,*,#836,.T.);
#876=EDGE_LOOP('',(#860,#868,#874,#875));
#877=FACE_BOUND('',#876,.T.);
#878=ADVANCED_FACE('F258',(#877),#852,.F.);
#879=CARTESIAN_POINT('',(-22.1361,8.69949999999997,12.7));
#880=DIRECTION('',(0.,0.,-1.));
#881=DIRECTION('',(-1.,0.,0.));
#882=AXIS2_PLACEMENT_3D('',#879,#880,#881);
#883=CYLINDRICAL_SURFACE('',#882,4.4958);
#884=CARTESIAN_POINT('',(-22.1361,8.69949999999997,-12.7));
#885=DIRECTION('',(0.,0.,1.));
#886=DIRECTION('',(1.,0.,0.));
#887=AXIS2_PLACEMENT_3D('',#884,#885,#886);
#888=CIRCLE('',#887,4.4958);
#889=EDGE_CURVE('E148',#858,#29,#888,.T.);
#890=ORIENTED_EDGE('',*,*,#889,.T.);
#891=ORIENTED_EDGE('',*,*,#54,.F.);
#892=CARTESIAN_POINT('',(-22.1361,8.69949999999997,12.7));
#893=DIRECTION('',(0.,0.,1.));
#894=DIRECTION('',(1.,0.,0.));
#895=AXIS2_PLACEMENT_3D('',#892,#893,#894);
#896=CIRCLE('',#895,4.4958);
#897=EDGE_CURVE('E55',#866,#47,#896,.T.);
#898=ORIENTED_EDGE('',*,*,#897,.F.);
#899=ORIENTED_EDGE('',*,*,#867,.T.);
#900=EDGE_LOOP('',(#890,#891,#898,#899));
#901=FACE_BOUND('',#900,.T.);
#902=ADVANCED_FACE('F470',(#901),#883,.T.);
#903=CARTESIAN_POINT('',(-22.1361,8.69949999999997,12.7));
#904=DIRECTION('',(0.,0.,1.));
#905=DIRECTION('',(1.,0.,0.));
#906=AXIS2_PLACEMENT_3D('',#903,#904,#905);
#907=PLANE('',#906);
#908=DIRECTION('',(0.,-1.,0.));
#909=VECTOR('',#908,1.);
#910=CARTESIAN_POINT('',(20.6375,19.1389,12.7));
#911=LINE('',#910,#909);
#912=EDGE_CURVE('E2131',#471,#480,#911,.T.);
#913=ORIENTED_EDGE('',*,*,#912,.T.);
#914=ORIENTED_EDGE('',*,*,#481,.T.);
#915=EDGE_LOOP('',(#913,#914));
#916=FACE_BOUND('',#915,.T.);
#917=CARTESIAN_POINT('',(22.1361,19.1389,12.7));
#918=DIRECTION('',(0.,0.,1.));
#919=DIRECTION('',(-1.,0.,0.));
#920=AXIS2_PLACEMENT_3D('',#917,#918,#919);
#921=CIRCLE('',#920,1.4986);
#922=CARTESIAN_POINT('',(22.1361,20.6375,12.7));
#923=VERTEX_POINT('',#922);
#924=EDGE_CURVE('E2129',#923,#522,#921,.T.);
#925=ORIENTED_EDGE('',*,*,#924,.T.);
#926=ORIENTED_EDGE('',*,*,#523,.T.);
#927=ORIENTED_EDGE('',*,*,#559,.T.);
#928=ORIENTED_EDGE('',*,*,#592,.T.);
#929=ORIENTED_EDGE('',*,*,#623,.T.);
#930=ORIENTED_EDGE('',*,*,#654,.T.);
#931=ORIENTED_EDGE('',*,*,#685,.T.);
#932=ORIENTED_EDGE('',*,*,#716,.T.);
#933=ORIENTED_EDGE('',*,*,#747,.T.);
#934=ORIENTED_EDGE('',*,*,#780,.T.);
#935=ORIENTED_EDGE('',*,*,#811,.T.);
#936=ORIENTED_EDGE('',*,*,#842,.T.);
#937=ORIENTED_EDGE('',*,*,#873,.T.);
#938=ORIENTED_EDGE('',*,*,#897,.T.);
#939=ORIENTED_EDGE('',*,*,#48,.T.);
#940=ORIENTED_EDGE('',*,*,#84,.T.);
#941=ORIENTED_EDGE('',*,*,#115,.T.);
#942=ORIENTED_EDGE('',*,*,#146,.T.);
#943=ORIENTED_EDGE('',*,*,#177,.T.);
#944=ORIENTED_EDGE('',*,*,#210,.T.);
#945=ORIENTED_EDGE('',*,*,#241,.T.);
#946=ORIENTED_EDGE('',*,*,#274,.T.);
#947=ORIENTED_EDGE('',*,*,#305,.T.);
#948=ORIENTED_EDGE('',*,*,#338,.T.);
#949=ORIENTED_EDGE('',*,*,#369,.T.);
#950=ORIENTED_EDGE('',*,*,#402,.T.);
#951=CARTESIAN_POINT('',(-19.1389,-1.4986,12.7));
#952=DIRECTION('',(0.,0.,-1.));
#953=DIRECTION('',(-1.,0.,0.));
#954=AXIS2_PLACEMENT_3D('',#951,#952,#953);
#955=CIRCLE('',#954,1.4986);
#956=CARTESIAN_POINT('',(-20.6375,-1.4986,12.7));
#957=VERTEX_POINT('',#956);
#958=EDGE_CURVE('E1586',#957,#394,#955,.T.);
#959=ORIENTED_EDGE('',*,*,#958,.F.);
#960=DIRECTION('',(0.,1.,0.));
#961=VECTOR('',#960,1.);
#962=CARTESIAN_POINT('',(-20.6375,-6.10384865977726,12.7));
#963=LINE('',#962,#961);
#964=CARTESIAN_POINT('',(-20.6375,-6.10384865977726,12.7));
#965=VERTEX_POINT('',#964);
#966=EDGE_CURVE('E1589',#965,#957,#963,.T.);
#967=ORIENTED_EDGE('',*,*,#966,.F.);
#968=CARTESIAN_POINT('',(-22.1361,-8.69949999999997,12.7));
#969=DIRECTION('',(0.,0.,1.));
#970=DIRECTION('',(1.,0.,0.));
#971=AXIS2_PLACEMENT_3D('',#968,#969,#970);
#972=CIRCLE('',#971,2.9972);
#973=CARTESIAN_POINT('',(-20.6375,-11.2951513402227,12.7));
#974=VERTEX_POINT('',#973);
#975=EDGE_CURVE('E1592',#974,#965,#972,.T.);
#976=ORIENTED_EDGE('',*,*,#975,.F.);
#977=DIRECTION('',(0.,1.,0.));
#978=VECTOR('',#977,1.);
#979=CARTESIAN_POINT('',(-20.6375,-19.1389,12.7));
#980=LINE('',#979,#978);
#981=CARTESIAN_POINT('',(-20.6375,-19.1389,12.7));
#982=VERTEX_POINT('',#981);
#983=EDGE_CURVE('E1595',#982,#974,#980,.T.);
#984=ORIENTED_EDGE('',*,*,#983,.F.);
#985=CARTESIAN_POINT('',(-19.1389,-19.1389,12.7));
#986=DIRECTION('',(0.,0.,-1.));
#987=DIRECTION('',(-1.,0.,0.));
#988=AXIS2_PLACEMENT_3D('',#985,#986,#987);
#989=CIRCLE('',#988,1.4986);
#990=CARTESIAN_POINT('',(-19.1389,-20.6375,12.7));
#991=VERTEX_POINT('',#990);
#992=EDGE_CURVE('E1598',#991,#982,#989,.T.);
#993=ORIENTED_EDGE('',*,*,#992,.F.);
#994=DIRECTION('',(-1.,0.,0.));
#995=VECTOR('',#994,1.);
#996=CARTESIAN_POINT('',(-19.1389,-20.6375,12.7));
#997=LINE('',#996,#995);
#998=CARTESIAN_POINT('',(-12.6111,-20.6375,12.7));
#999=VERTEX_POINT('',#998);
#1000=EDGE_CURVE('E1601',#999,#991,#997,.T.);
#1001=ORIENTED_EDGE('',*,*,#1000,.F.);
#1002=CARTESIAN_POINT('',(-12.6111,-19.1389,12.7));
#1003=DIRECTION('',(0.,0.,-1.));
#1004=DIRECTION('',(-1.,0.,0.));
#1005=AXIS2_PLACEMENT_3D('',#1002,#1003,#1004);
#1006=CIRCLE('',#1005,1.4986);
#1007=CARTESIAN_POINT('',(-11.1125,-19.1389,12.7));
#1008=VERTEX_POINT('',#1007);
#1009=EDGE_CURVE('E1604',#1008,#999,#1006,.T.);
#1010=ORIENTED_EDGE('',*,*,#1009,.F.);
#1011=DIRECTION('',(0.,-1.,0.));
#1012=VECTOR('',#1011,1.);
#1013=CARTESIAN_POINT('',(-11.1125,-19.1389,12.7));
#1014=LINE('',#1013,#1012);
#1015=CARTESIAN_POINT('',(-11.1125,-14.2875,12.7));
#1016=VERTEX_POINT('',#1015);
#1017=EDGE_CURVE('E1607',#1016,#1008,#1014,.T.);
#1018=ORIENTED_EDGE('',*,*,#1017,.F.);
#1019=DIRECTION('',(1.,0.,0.));
#1020=VECTOR('',#1019,1.);
#1021=CARTESIAN_POINT('',(-12.6111,-14.2875,12.7));
#1022=LINE('',#1021,#1020);
#1023=CARTESIAN_POINT('',(-12.6111,-14.2875,12.7));
#1024=VERTEX_POINT('',#1023);
#1025=EDGE_CURVE('E1610',#1024,#1016,#1022,.T.);
#1026=ORIENTED_EDGE('',*,*,#1025,.F.);
#1027=DIRECTION('',(0.,1.,0.));
#1028=VECTOR('',#1027,1.);
#1029=CARTESIAN_POINT('',(-12.6111,-19.1389,12.7));
#1030=LINE('',#1029,#1028);
#1031=CARTESIAN_POINT('',(-12.6111,-19.1389,12.7));
#1032=VERTEX_POINT('',#1031);
#1033=EDGE_CURVE('E1613',#1032,#1024,#1030,.T.);
#1034=ORIENTED_EDGE('',*,*,#1033,.F.);
#1035=DIRECTION('',(1.,0.,0.));
#1036=VECTOR('',#1035,1.);
#1037=CARTESIAN_POINT('',(-19.1389,-19.1389,12.7));
#1038=LINE('',#1037,#1036);
#1039=CARTESIAN_POINT('',(-19.1389,-19.1389,12.7));
#1040=VERTEX_POINT('',#1039);
#1041=EDGE_CURVE('E1616',#1040,#1032,#1038,.T.);
#1042=ORIENTED_EDGE('',*,*,#1041,.F.);
#1043=DIRECTION('',(0.,-1.,0.));
#1044=VECTOR('',#1043,1.);
#1045=CARTESIAN_POINT('',(-19.1389,-19.1389,12.7));
#1046=LINE('',#1045,#1044);
#1047=CARTESIAN_POINT('',(-19.1389,-12.0504714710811,12.7));
#1048=VERTEX_POINT('',#1047);
#1049=EDGE_CURVE('E1537',#1048,#1040,#1046,.T.);
#1050=ORIENTED_EDGE('',*,*,#1049,.F.);
#1051=CARTESIAN_POINT('',(-22.1361,-8.69949999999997,12.7));
#1052=DIRECTION('',(0.,0.,-1.));
#1053=DIRECTION('',(1.,0.,0.));
#1054=AXIS2_PLACEMENT_3D('',#1051,#1052,#1053);
#1055=CIRCLE('',#1054,4.4958);
#1056=CARTESIAN_POINT('',(-19.1389,-5.34852852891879,12.7));
#1057=VERTEX_POINT('',#1056);
#1058=EDGE_CURVE('E1540',#1057,#1048,#1055,.T.);
#1059=ORIENTED_EDGE('',*,*,#1058,.F.);
#1060=DIRECTION('',(0.,-1.,0.));
#1061=VECTOR('',#1060,1.);
#1062=CARTESIAN_POINT('',(-19.1389,-5.34852852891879,12.7));
#1063=LINE('',#1062,#1061);
#1064=CARTESIAN_POINT('',(-19.1389,-1.4986,12.7));
#1065=VERTEX_POINT('',#1064);
#1066=EDGE_CURVE('E1544',#1065,#1057,#1063,.T.);
#1067=ORIENTED_EDGE('',*,*,#1066,.F.);
#1068=DIRECTION('',(-1.,0.,0.));
#1069=VECTOR('',#1068,1.);
#1070=CARTESIAN_POINT('',(-19.1389,-1.4986,12.7));
#1071=LINE('',#1070,#1069);
#1072=CARTESIAN_POINT('',(19.1389,-1.49860000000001,12.7));
#1073=VERTEX_POINT('',#1072);
#1074=EDGE_CURVE('E1547',#1073,#1065,#1071,.T.);
#1075=ORIENTED_EDGE('',*,*,#1074,.F.);
#1076=DIRECTION('',(0.,1.,0.));
#1077=VECTOR('',#1076,1.);
#1078=CARTESIAN_POINT('',(19.1389,-1.49860000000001,12.7));
#1079=LINE('',#1078,#1077);
#1080=CARTESIAN_POINT('',(19.1389,-5.34852852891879,12.7));
#1081=VERTEX_POINT('',#1080);
#1082=EDGE_CURVE('E1550',#1081,#1073,#1079,.T.);
#1083=ORIENTED_EDGE('',*,*,#1082,.F.);
#1084=CARTESIAN_POINT('',(22.1361,-8.69949999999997,12.7));
#1085=DIRECTION('',(0.,0.,-1.));
#1086=DIRECTION('',(1.,0.,0.));
#1087=AXIS2_PLACEMENT_3D('',#1084,#1085,#1086);
#1088=CIRCLE('',#1087,4.4958);
#1089=CARTESIAN_POINT('',(19.1389,-12.0504714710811,12.7));
#1090=VERTEX_POINT('',#1089);
#1091=EDGE_CURVE('E1553',#1090,#1081,#1088,.T.);
#1092=ORIENTED_EDGE('',*,*,#1091,.F.);
#1093=DIRECTION('',(0.,1.,0.));
#1094=VECTOR('',#1093,1.);
#1095=CARTESIAN_POINT('',(19.1389,-12.0504714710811,12.7));
#1096=LINE('',#1095,#1094);
#1097=CARTESIAN_POINT('',(19.1389,-19.1389,12.7));
#1098=VERTEX_POINT('',#1097);
#1099=EDGE_CURVE('E1556',#1098,#1090,#1096,.T.);
#1100=ORIENTED_EDGE('',*,*,#1099,.F.);
#1101=DIRECTION('',(1.,0.,0.));
#1102=VECTOR('',#1101,1.);
#1103=CARTESIAN_POINT('',(19.1389,-19.1389,12.7));
#1104=LINE('',#1103,#1102);
#1105=CARTESIAN_POINT('',(12.6111,-19.1389,12.7));
#1106=VERTEX_POINT('',#1105);
#1107=EDGE_CURVE('E1559',#1106,#1098,#1104,.T.);
#1108=ORIENTED_EDGE('',*,*,#1107,.F.);
#1109=DIRECTION('',(0.,-1.,0.));
#1110=VECTOR('',#1109,1.);
#1111=CARTESIAN_POINT('',(12.6111,-19.1389,12.7));
#1112=LINE('',#1111,#1110);
#1113=CARTESIAN_POINT('',(12.6111,-14.2875,12.7));
#1114=VERTEX_POINT('',#1113);
#1115=EDGE_CURVE('E1562',#1114,#1106,#1112,.T.);
#1116=ORIENTED_EDGE('',*,*,#1115,.F.);
#1117=DIRECTION('',(1.,0.,0.));
#1118=VECTOR('',#1117,1.);
#1119=CARTESIAN_POINT('',(11.1125,-14.2875,12.7));
#1120=LINE('',#1119,#1118);
#1121=CARTESIAN_POINT('',(11.1125,-14.2875,12.7));
#1122=VERTEX_POINT('',#1121);
#1123=EDGE_CURVE('E1565',#1122,#1114,#1120,.T.);
#1124=ORIENTED_EDGE('',*,*,#1123,.F.);
#1125=DIRECTION('',(0.,1.,0.));
#1126=VECTOR('',#1125,1.);
#1127=CARTESIAN_POINT('',(11.1125,-19.1389,12.7));
#1128=LINE('',#1127,#1126);
#1129=CARTESIAN_POINT('',(11.1125,-19.1389,12.7));
#1130=VERTEX_POINT('',#1129);
#1131=EDGE_CURVE('E1568',#1130,#1122,#1128,.T.);
#1132=ORIENTED_EDGE('',*,*,#1131,.F.);
#1133=CARTESIAN_POINT('',(12.6111,-19.1389,12.7));
#1134=DIRECTION('',(0.,0.,-1.));
#1135=DIRECTION('',(-1.,0.,0.));
#1136=AXIS2_PLACEMENT_3D('',#1133,#1134,#1135);
#1137=CIRCLE('',#1136,1.4986);
#1138=CARTESIAN_POINT('',(12.6111,-20.6375,12.7));
#1139=VERTEX_POINT('',#1138);
#1140=EDGE_CURVE('E1571',#1139,#1130,#1137,.T.);
#1141=ORIENTED_EDGE('',*,*,#1140,.F.);
#1142=DIRECTION('',(-1.,0.,0.));
#1143=VECTOR('',#1142,1.);
#1144=CARTESIAN_POINT('',(19.1389,-20.6375,12.7));
#1145=LINE('',#1144,#1143);
#1146=CARTESIAN_POINT('',(19.1389,-20.6375,12.7));
#1147=VERTEX_POINT('',#1146);
#1148=EDGE_CURVE('E1574',#1147,#1139,#1145,.T.);
#1149=ORIENTED_EDGE('',*,*,#1148,.F.);
#1150=CARTESIAN_POINT('',(19.1389,-19.1389,12.7));
#1151=DIRECTION('',(0.,0.,-1.));
#1152=DIRECTION('',(-1.,0.,0.));
#1153=AXIS2_PLACEMENT_3D('',#1150,#1151,#1152);
#1154=CIRCLE('',#1153,1.4986);
#1155=CARTESIAN_POINT('',(20.6375,-19.1389,12.7));
#1156=VERTEX_POINT('',#1155);
#1157=EDGE_CURVE('E1577',#1156,#1147,#1154,.T.);
#1158=ORIENTED_EDGE('',*,*,#1157,.F.);
#1159=CARTESIAN_POINT('',(22.1361,-19.1389,12.7));
#1160=DIRECTION('',(0.,0.,1.));
#1161=DIRECTION('',(-1.,0.,0.));
#1162=AXIS2_PLACEMENT_3D('',#1159,#1160,#1161);
#1163=CIRCLE('',#1162,1.4986);
#1164=CARTESIAN_POINT('',(22.1361,-20.6375,12.7));
#1165=VERTEX_POINT('',#1164);
#1166=EDGE_CURVE('E1989',#1156,#1165,#1163,.T.);
#1167=ORIENTED_EDGE('',*,*,#1166,.T.);
#1168=DIRECTION('',(1.,0.,0.));
#1169=VECTOR('',#1168,1.);
#1170=CARTESIAN_POINT('',(22.1361,-20.6375,12.7));
#1171=LINE('',#1170,#1169);
#1172=CARTESIAN_POINT('',(26.7413486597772,-20.6375,12.7));
#1173=VERTEX_POINT('',#1172);
#1174=EDGE_CURVE('E2012',#1165,#1173,#1171,.T.);
#1175=ORIENTED_EDGE('',*,*,#1174,.T.);
#1176=CARTESIAN_POINT('',(29.337,-22.1361,12.7));
#1177=DIRECTION('',(0.,0.,-1.));
#1178=DIRECTION('',(1.,0.,0.));
#1179=AXIS2_PLACEMENT_3D('',#1176,#1177,#1178);
#1180=CIRCLE('',#1179,2.9972);
#1181=CARTESIAN_POINT('',(31.9326513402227,-20.6375,12.7));
#1182=VERTEX_POINT('',#1181);
#1183=EDGE_CURVE('E2005',#1173,#1182,#1180,.T.);
#1184=ORIENTED_EDGE('',*,*,#1183,.T.);
#1185=DIRECTION('',(1.,0.,0.));
#1186=VECTOR('',#1185,1.);
#1187=CARTESIAN_POINT('',(31.9326513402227,-20.6375,12.7));
#1188=LINE('',#1187,#1186);
#1189=CARTESIAN_POINT('',(39.7764,-20.6375,12.7));
#1190=VERTEX_POINT('',#1189);
#1191=EDGE_CURVE('E2011',#1182,#1190,#1188,.T.);
#1192=ORIENTED_EDGE('',*,*,#1191,.T.);
#1193=CARTESIAN_POINT('',(39.7764,-19.1389,12.7));
#1194=DIRECTION('',(0.,0.,1.));
#1195=DIRECTION('',(-1.,0.,0.));
#1196=AXIS2_PLACEMENT_3D('',#1193,#1194,#1195);
#1197=CIRCLE('',#1196,1.4986);
#1198=CARTESIAN_POINT('',(41.275,-19.1389,12.7));
#1199=VERTEX_POINT('',#1198);
#1200=EDGE_CURVE('E2014',#1190,#1199,#1197,.T.);
#1201=ORIENTED_EDGE('',*,*,#1200,.T.);
#1202=DIRECTION('',(0.,1.,0.));
#1203=VECTOR('',#1202,1.);
#1204=CARTESIAN_POINT('',(41.275,-19.1389,12.7));
#1205=LINE('',#1204,#1203);
#1206=CARTESIAN_POINT('',(41.275,-12.6111,12.7));
#1207=VERTEX_POINT('',#1206);
#1208=EDGE_CURVE('E2021',#1199,#1207,#1205,.T.);
#1209=ORIENTED_EDGE('',*,*,#1208,.T.);
#1210=CARTESIAN_POINT('',(39.7764,-12.6111,12.7));
#1211=DIRECTION('',(0.,0.,1.));
#1212=DIRECTION('',(-1.,0.,0.));
#1213=AXIS2_PLACEMENT_3D('',#1210,#1211,#1212);
#1214=CIRCLE('',#1213,1.49859999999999);
#1215=CARTESIAN_POINT('',(39.7764,-11.1125,12.7));
#1216=VERTEX_POINT('',#1215);
#1217=EDGE_CURVE('E2024',#1207,#1216,#1214,.T.);
#1218=ORIENTED_EDGE('',*,*,#1217,.T.);
#1219=DIRECTION('',(-1.,0.,0.));
#1220=VECTOR('',#1219,1.);
#1221=CARTESIAN_POINT('',(39.7764,-11.1125,12.7));
#1222=LINE('',#1221,#1220);
#1223=CARTESIAN_POINT('',(34.925,-11.1125,12.7));
#1224=VERTEX_POINT('',#1223);
#1225=EDGE_CURVE('E2027',#1216,#1224,#1222,.T.);
#1226=ORIENTED_EDGE('',*,*,#1225,.T.);
#1227=DIRECTION('',(0.,-1.,0.));
#1228=VECTOR('',#1227,1.);
#1229=CARTESIAN_POINT('',(34.925,-11.1125,12.7));
#1230=LINE('',#1229,#1228);
#1231=CARTESIAN_POINT('',(34.925,-12.6111,12.7));
#1232=VERTEX_POINT('',#1231);
#1233=EDGE_CURVE('E2030',#1224,#1232,#1230,.T.);
#1234=ORIENTED_EDGE('',*,*,#1233,.T.);
#1235=DIRECTION('',(1.,0.,0.));
#1236=VECTOR('',#1235,1.);
#1237=CARTESIAN_POINT('',(39.7764,-12.6111,12.7));
#1238=LINE('',#1237,#1236);
#1239=CARTESIAN_POINT('',(39.7764,-12.6111,12.7));
#1240=VERTEX_POINT('',#1239);
#1241=EDGE_CURVE('E2033',#1232,#1240,#1238,.T.);
#1242=ORIENTED_EDGE('',*,*,#1241,.T.);
#1243=DIRECTION('',(0.,-1.,0.));
#1244=VECTOR('',#1243,1.);
#1245=CARTESIAN_POINT('',(39.7764,-19.1389,12.7));
#1246=LINE('',#1245,#1244);
#1247=CARTESIAN_POINT('',(39.7764,-19.1389,12.7));
#1248=VERTEX_POINT('',#1247);
#1249=EDGE_CURVE('E2036',#1240,#1248,#1246,.T.);
#1250=ORIENTED_EDGE('',*,*,#1249,.T.);
#1251=DIRECTION('',(-1.,0.,0.));
#1252=VECTOR('',#1251,1.);
#1253=CARTESIAN_POINT('',(32.6879714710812,-19.1389,12.7));
#1254=LINE('',#1253,#1252);
#1255=CARTESIAN_POINT('',(32.6879714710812,-19.1389,12.7));
#1256=VERTEX_POINT('',#1255);
#1257=EDGE_CURVE('E2039',#1248,#1256,#1254,.T.);
#1258=ORIENTED_EDGE('',*,*,#1257,.T.);
#1259=CARTESIAN_POINT('',(29.337,-22.1361,12.7));
#1260=DIRECTION('',(0.,0.,1.));
#1261=DIRECTION('',(1.,0.,0.));
#1262=AXIS2_PLACEMENT_3D('',#1259,#1260,#1261);
#1263=CIRCLE('',#1262,4.4958);
#1264=CARTESIAN_POINT('',(25.9860285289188,-19.1389,12.7));
#1265=VERTEX_POINT('',#1264);
#1266=EDGE_CURVE('E2042',#1256,#1265,#1263,.T.);
#1267=ORIENTED_EDGE('',*,*,#1266,.T.);
#1268=DIRECTION('',(-1.,0.,0.));
#1269=VECTOR('',#1268,1.);
#1270=CARTESIAN_POINT('',(22.1361,-19.1389,12.7));
#1271=LINE('',#1270,#1269);
#1272=CARTESIAN_POINT('',(22.1361,-19.1389,12.7));
#1273=VERTEX_POINT('',#1272);
#1274=EDGE_CURVE('E2045',#1265,#1273,#1271,.T.);
#1275=ORIENTED_EDGE('',*,*,#1274,.T.);
#1276=DIRECTION('',(0.,1.,0.));
#1277=VECTOR('',#1276,1.);
#1278=CARTESIAN_POINT('',(22.1361,19.1389,12.7));
#1279=LINE('',#1278,#1277);
#1280=CARTESIAN_POINT('',(22.1361,19.1389,12.7));
#1281=VERTEX_POINT('',#1280);
#1282=EDGE_CURVE('E2048',#1273,#1281,#1279,.T.);
#1283=ORIENTED_EDGE('',*,*,#1282,.T.);
#1284=DIRECTION('',(1.,0.,0.));
#1285=VECTOR('',#1284,1.);
#1286=CARTESIAN_POINT('',(25.9860285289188,19.1389,12.7));
#1287=LINE('',#1286,#1285);
#1288=CARTESIAN_POINT('',(25.9860285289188,19.1389,12.7));
#1289=VERTEX_POINT('',#1288);
#1290=EDGE_CURVE('E2050',#1281,#1289,#1287,.T.);
#1291=ORIENTED_EDGE('',*,*,#1290,.T.);
#1292=CARTESIAN_POINT('',(29.337,22.1361,12.7));
#1293=DIRECTION('',(0.,0.,1.));
#1294=DIRECTION('',(1.,0.,0.));
#1295=AXIS2_PLACEMENT_3D('',#1292,#1293,#1294);
#1296=CIRCLE('',#1295,4.4958);
#1297=CARTESIAN_POINT('',(32.6879714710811,19.1389,12.7));
#1298=VERTEX_POINT('',#1297);
#1299=EDGE_CURVE('E1364',#1289,#1298,#1296,.T.);
#1300=ORIENTED_EDGE('',*,*,#1299,.T.);
#1301=DIRECTION('',(1.,0.,0.));
#1302=VECTOR('',#1301,1.);
#1303=CARTESIAN_POINT('',(39.7764,19.1389,12.7));
#1304=LINE('',#1303,#1302);
#1305=CARTESIAN_POINT('',(39.7764,19.1389,12.7));
#1306=VERTEX_POINT('',#1305);
#1307=EDGE_CURVE('E1356',#1298,#1306,#1304,.T.);
#1308=ORIENTED_EDGE('',*,*,#1307,.T.);
#1309=DIRECTION('',(0.,-1.,0.));
#1310=VECTOR('',#1309,1.);
#1311=CARTESIAN_POINT('',(39.7764,19.1389,12.7));
#1312=LINE('',#1311,#1310);
#1313=CARTESIAN_POINT('',(39.7764,12.6111,12.7));
#1314=VERTEX_POINT('',#1313);
#1315=EDGE_CURVE('E2225',#1306,#1314,#1312,.T.);
#1316=ORIENTED_EDGE('',*,*,#1315,.T.);
#1317=DIRECTION('',(-1.,0.,0.));
#1318=VECTOR('',#1317,1.);
#1319=CARTESIAN_POINT('',(39.7764,12.6111,12.7));
#1320=LINE('',#1319,#1318);
#1321=CARTESIAN_POINT('',(34.925,12.6111,12.7));
#1322=VERTEX_POINT('',#1321);
#1323=EDGE_CURVE('E2227',#1314,#1322,#1320,.T.);
#1324=ORIENTED_EDGE('',*,*,#1323,.T.);
#1325=DIRECTION('',(0.,-1.,0.));
#1326=VECTOR('',#1325,1.);
#1327=CARTESIAN_POINT('',(34.925,12.6111,12.7));
#1328=LINE('',#1327,#1326);
#1329=CARTESIAN_POINT('',(34.925,11.1125,12.7));
#1330=VERTEX_POINT('',#1329);
#1331=EDGE_CURVE('E2229',#1322,#1330,#1328,.T.);
#1332=ORIENTED_EDGE('',*,*,#1331,.T.);
#1333=DIRECTION('',(1.,0.,0.));
#1334=VECTOR('',#1333,1.);
#1335=CARTESIAN_POINT('',(39.7764,11.1125,12.7));
#1336=LINE('',#1335,#1334);
#1337=CARTESIAN_POINT('',(39.7764,11.1125,12.7));
#1338=VERTEX_POINT('',#1337);
#1339=EDGE_CURVE('E2234',#1330,#1338,#1336,.T.);
#1340=ORIENTED_EDGE('',*,*,#1339,.T.);
#1341=CARTESIAN_POINT('',(39.7764,12.6111,12.7));
#1342=DIRECTION('',(0.,0.,1.));
#1343=DIRECTION('',(-1.,0.,0.));
#1344=AXIS2_PLACEMENT_3D('',#1341,#1342,#1343);
#1345=CIRCLE('',#1344,1.4986);
#1346=CARTESIAN_POINT('',(41.275,12.6111,12.7));
#1347=VERTEX_POINT('',#1346);
#1348=EDGE_CURVE('E2236',#1338,#1347,#1345,.T.);
#1349=ORIENTED_EDGE('',*,*,#1348,.T.);
#1350=DIRECTION('',(0.,1.,0.));
#1351=VECTOR('',#1350,1.);
#1352=CARTESIAN_POINT('',(41.275,19.1389,12.7));
#1353=LINE('',#1352,#1351);
#1354=CARTESIAN_POINT('',(41.275,19.1389,12.7));
#1355=VERTEX_POINT('',#1354);
#1356=EDGE_CURVE('E2238',#1347,#1355,#1353,.T.);
#1357=ORIENTED_EDGE('',*,*,#1356,.T.);
#1358=CARTESIAN_POINT('',(39.7764,19.1389,12.7));
#1359=DIRECTION('',(0.,0.,1.));
#1360=DIRECTION('',(-1.,0.,0.));
#1361=AXIS2_PLACEMENT_3D('',#1358,#1359,#1360);
#1362=CIRCLE('',#1361,1.4986);
#1363=CARTESIAN_POINT('',(39.7764,20.6375,12.7));
#1364=VERTEX_POINT('',#1363);
#1365=EDGE_CURVE('E2240',#1355,#1364,#1362,.T.);
#1366=ORIENTED_EDGE('',*,*,#1365,.T.);
#1367=DIRECTION('',(-1.,0.,0.));
#1368=VECTOR('',#1367,1.);
#1369=CARTESIAN_POINT('',(39.7764,20.6375,12.7));
#1370=LINE('',#1369,#1368);
#1371=CARTESIAN_POINT('',(31.9326513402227,20.6375,12.7));
#1372=VERTEX_POINT('',#1371);
#1373=EDGE_CURVE('E2242',#1364,#1372,#1370,.T.);
#1374=ORIENTED_EDGE('',*,*,#1373,.T.);
#1375=CARTESIAN_POINT('',(29.337,22.1361,12.7));
#1376=DIRECTION('',(0.,0.,-1.));
#1377=DIRECTION('',(1.,0.,0.));
#1378=AXIS2_PLACEMENT_3D('',#1375,#1376,#1377);
#1379=CIRCLE('',#1378,2.9972);
#1380=CARTESIAN_POINT('',(26.7413486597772,20.6375,12.7));
#1381=VERTEX_POINT('',#1380);
#1382=EDGE_CURVE('E2244',#1372,#1381,#1379,.T.);
#1383=ORIENTED_EDGE('',*,*,#1382,.T.);
#1384=DIRECTION('',(-1.,0.,0.));
#1385=VECTOR('',#1384,1.);
#1386=CARTESIAN_POINT('',(26.7413486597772,20.6375,12.7));
#1387=LINE('',#1386,#1385);
#1388=EDGE_CURVE('E2134',#1381,#923,#1387,.T.);
#1389=ORIENTED_EDGE('',*,*,#1388,.T.);
#1390=EDGE_LOOP('',(#925,#926,#927,#928,#929,#930,#931,#932,#933,#934,#935,#936,#937,#938,#939,
#940,#941,#942,#943,#944,#945,#946,#947,#948,#949,#950,#959,#967,#976,#984,#993,#1001,#1010,
#1018,#1026,#1034,#1042,#1050,#1059,#1067,#1075,#1083,#1092,#1100,#1108,#1116,#1124,#1132,#1141,
#1149,#1158,#1167,#1175,#1184,#1192,#1201,#1209,#1218,#1226,#1234,#1242,#1250,#1258,#1267,#1275,
#1283,#1291,#1300,#1308,#1316,#1324,#1332,#1340,#1349,#1357,#1366,#1374,#1383,#1389));
#1391=FACE_BOUND('',#1390,.T.);
#1392=ORIENTED_EDGE('',*,*,#439,.T.);
#1393=CARTESIAN_POINT('',(20.6375,-1.49860000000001,12.7));
#1394=VERTEX_POINT('',#1393);
#1395=EDGE_CURVE('E2128',#429,#1394,#911,.T.);
#1396=ORIENTED_EDGE('',*,*,#1395,.T.);
#1397=CARTESIAN_POINT('',(19.1389,-1.49860000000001,12.7));
#1398=DIRECTION('',(0.,0.,-1.));
#1399=DIRECTION('',(-1.,0.,0.));
#1400=AXIS2_PLACEMENT_3D('',#1397,#1398,#1399);
#1401=CIRCLE('',#1400,1.4986);
#1402=EDGE_CURVE('E1583',#438,#1394,#1401,.T.);
#1403=ORIENTED_EDGE('',*,*,#1402,.F.);
#1404=EDGE_LOOP('',(#1392,#1396,#1403));
#1405=FACE_BOUND('',#1404,.T.);
#1406=CARTESIAN_POINT('',(20.6375,-6.10384865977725,12.7));
#1407=VERTEX_POINT('',#1406);
#1408=CARTESIAN_POINT('',(20.6375,-11.2951513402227,12.7));
#1409=VERTEX_POINT('',#1408);
#1410=EDGE_CURVE('E2122',#1407,#1409,#911,.T.);
#1411=ORIENTED_EDGE('',*,*,#1410,.T.);
#1412=CARTESIAN_POINT('',(22.1361,-8.69949999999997,12.7));
#1413=DIRECTION('',(0.,0.,1.));
#1414=DIRECTION('',(1.,0.,0.));
#1415=AXIS2_PLACEMENT_3D('',#1412,#1413,#1414);
#1416=CIRCLE('',#1415,2.9972);
#1417=EDGE_CURVE('E1580',#1407,#1409,#1416,.T.);
#1418=ORIENTED_EDGE('',*,*,#1417,.F.);
#1419=EDGE_LOOP('',(#1411,#1418));
#1420=FACE_BOUND('',#1419,.T.);
#1421=ADVANCED_FACE('F241',(#916,#1391,#1405,#1420),#907,.T.);
#1422=CARTESIAN_POINT('',(-22.1361,8.69949999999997,-12.7));
#1423=DIRECTION('',(0.,0.,1.));
#1424=DIRECTION('',(1.,0.,0.));
#1425=AXIS2_PLACEMENT_3D('',#1422,#1423,#1424);
#1426=PLANE('',#1425);
#1427=ORIENTED_EDGE('',*,*,#464,.F.);
#1428=DIRECTION('',(0.,-1.,0.));
#1429=VECTOR('',#1428,1.);
#1430=CARTESIAN_POINT('',(20.6375,19.1389,-12.7));
#1431=LINE('',#1430,#1429);
#1432=EDGE_CURVE('E1410',#463,#461,#1431,.T.);
#1433=ORIENTED_EDGE('',*,*,#1432,.F.);
#1434=EDGE_LOOP('',(#1427,#1433));
#1435=FACE_BOUND('',#1434,.T.);
#1436=ORIENTED_EDGE('',*,*,#506,.F.);
#1437=CARTESIAN_POINT('',(22.1361,19.1389,-12.7));
#1438=DIRECTION('',(0.,0.,1.));
#1439=DIRECTION('',(-1.,0.,0.));
#1440=AXIS2_PLACEMENT_3D('',#1437,#1438,#1439);
#1441=CIRCLE('',#1440,1.4986);
#1442=CARTESIAN_POINT('',(22.1361,20.6375,-12.7));
#1443=VERTEX_POINT('',#1442);
#1444=EDGE_CURVE('E1403',#1443,#503,#1441,.T.);
#1445=ORIENTED_EDGE('',*,*,#1444,.F.);
#1446=DIRECTION('',(-1.,0.,0.));
#1447=VECTOR('',#1446,1.);
#1448=CARTESIAN_POINT('',(26.7413486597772,20.6375,-12.7));
#1449=LINE('',#1448,#1447);
#1450=CARTESIAN_POINT('',(26.7413486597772,20.6375,-12.7));
#1451=VERTEX_POINT('',#1450);
#1452=EDGE_CURVE('E1400',#1451,#1443,#1449,.T.);
#1453=ORIENTED_EDGE('',*,*,#1452,.F.);
#1454=CARTESIAN_POINT('',(29.337,22.1361,-12.7));
#1455=DIRECTION('',(0.,0.,-1.));
#1456=DIRECTION('',(1.,0.,0.));
#1457=AXIS2_PLACEMENT_3D('',#1454,#1455,#1456);
#1458=CIRCLE('',#1457,2.9972);
#1459=CARTESIAN_POINT('',(31.9326513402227,20.6375,-12.7));
#1460=VERTEX_POINT('',#1459);
#1461=EDGE_CURVE('E1397',#1460,#1451,#1458,.T.);
#1462=ORIENTED_EDGE('',*,*,#1461,.F.);
#1463=DIRECTION('',(-1.,0.,0.));
#1464=VECTOR('',#1463,1.);
#1465=CARTESIAN_POINT('',(39.7764,20.6375,-12.7));
#1466=LINE('',#1465,#1464);
#1467=CARTESIAN_POINT('',(39.7764,20.6375,-12.7));
#1468=VERTEX_POINT('',#1467);
#1469=EDGE_CURVE('E1394',#1468,#1460,#1466,.T.);
#1470=ORIENTED_EDGE('',*,*,#1469,.F.);
#1471=CARTESIAN_POINT('',(39.7764,19.1389,-12.7));
#1472=DIRECTION('',(0.,0.,1.));
#1473=DIRECTION('',(-1.,0.,0.));
#1474=AXIS2_PLACEMENT_3D('',#1471,#1472,#1473);
#1475=CIRCLE('',#1474,1.4986);
#1476=CARTESIAN_POINT('',(41.275,19.1389,-12.7));
#1477=VERTEX_POINT('',#1476);
#1478=EDGE_CURVE('E1391',#1477,#1468,#1475,.T.);
#1479=ORIENTED_EDGE('',*,*,#1478,.F.);
#1480=DIRECTION('',(0.,1.,0.));
#1481=VECTOR('',#1480,1.);
#1482=CARTESIAN_POINT('',(41.275,19.1389,-12.7));
#1483=LINE('',#1482,#1481);
#1484=CARTESIAN_POINT('',(41.275,12.6111,-12.7));
#1485=VERTEX_POINT('',#1484);
#1486=EDGE_CURVE('E1388',#1485,#1477,#1483,.T.);
#1487=ORIENTED_EDGE('',*,*,#1486,.F.);
#1488=CARTESIAN_POINT('',(39.7764,12.6111,-12.7));
#1489=DIRECTION('',(0.,0.,1.));
#1490=DIRECTION('',(-1.,0.,0.));
#1491=AXIS2_PLACEMENT_3D('',#1488,#1489,#1490);
#1492=CIRCLE('',#1491,1.4986);
#1493=CARTESIAN_POINT('',(39.7764,11.1125,-12.7));
#1494=VERTEX_POINT('',#1493);
#1495=EDGE_CURVE('E1385',#1494,#1485,#1492,.T.);
#1496=ORIENTED_EDGE('',*,*,#1495,.F.);
#1497=DIRECTION('',(1.,0.,0.));
#1498=VECTOR('',#1497,1.);
#1499=CARTESIAN_POINT('',(39.7764,11.1125,-12.7));
#1500=LINE('',#1499,#1498);
#1501=CARTESIAN_POINT('',(34.925,11.1125,-12.7));
#1502=VERTEX_POINT('',#1501);
#1503=EDGE_CURVE('E1382',#1502,#1494,#1500,.T.);
#1504=ORIENTED_EDGE('',*,*,#1503,.F.);
#1505=DIRECTION('',(0.,-1.,0.));
#1506=VECTOR('',#1505,1.);
#1507=CARTESIAN_POINT('',(34.925,12.6111,-12.7));
#1508=LINE('',#1507,#1506);
#1509=CARTESIAN_POINT('',(34.925,12.6111,-12.7));
#1510=VERTEX_POINT('',#1509);
#1511=EDGE_CURVE('E1379',#1510,#1502,#1508,.T.);
#1512=ORIENTED_EDGE('',*,*,#1511,.F.);
#1513=DIRECTION('',(-1.,0.,0.));
#1514=VECTOR('',#1513,1.);
#1515=CARTESIAN_POINT('',(39.7764,12.6111,-12.7));
#1516=LINE('',#1515,#1514);
#1517=CARTESIAN_POINT('',(39.7764,12.6111,-12.7));
#1518=VERTEX_POINT('',#1517);
#1519=EDGE_CURVE('E1372',#1518,#1510,#1516,.T.);
#1520=ORIENTED_EDGE('',*,*,#1519,.F.);
#1521=DIRECTION('',(0.,-1.,0.));
#1522=VECTOR('',#1521,1.);
#1523=CARTESIAN_POINT('',(39.7764,19.1389,-12.7));
#1524=LINE('',#1523,#1522);
#1525=CARTESIAN_POINT('',(39.7764,19.1389,-12.7));
#1526=VERTEX_POINT('',#1525);
#1527=EDGE_CURVE('E1369',#1526,#1518,#1524,.T.);
#1528=ORIENTED_EDGE('',*,*,#1527,.F.);
#1529=DIRECTION('',(1.,0.,0.));
#1530=VECTOR('',#1529,1.);
#1531=CARTESIAN_POINT('',(39.7764,19.1389,-12.7));
#1532=LINE('',#1531,#1530);
#1533=CARTESIAN_POINT('',(32.6879714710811,19.1389,-12.7));
#1534=VERTEX_POINT('',#1533);
#1535=EDGE_CURVE('E1362',#1534,#1526,#1532,.T.);
#1536=ORIENTED_EDGE('',*,*,#1535,.F.);
#1537=CARTESIAN_POINT('',(29.337,22.1361,-12.7));
#1538=DIRECTION('',(0.,0.,1.));
#1539=DIRECTION('',(1.,0.,0.));
#1540=AXIS2_PLACEMENT_3D('',#1537,#1538,#1539);
#1541=CIRCLE('',#1540,4.4958);
#1542=CARTESIAN_POINT('',(25.9860285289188,19.1389,-12.7));
#1543=VERTEX_POINT('',#1542);
#1544=EDGE_CURVE('E1343',#1543,#1534,#1541,.T.);
#1545=ORIENTED_EDGE('',*,*,#1544,.F.);
#1546=DIRECTION('',(1.,0.,0.));
#1547=VECTOR('',#1546,1.);
#1548=CARTESIAN_POINT('',(25.9860285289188,19.1389,-12.7));
#1549=LINE('',#1548,#1547);
#1550=CARTESIAN_POINT('',(22.1361,19.1389,-12.7));
#1551=VERTEX_POINT('',#1550);
#1552=EDGE_CURVE('E1357',#1551,#1543,#1549,.T.);
#1553=ORIENTED_EDGE('',*,*,#1552,.F.);
#1554=DIRECTION('',(0.,1.,0.));
#1555=VECTOR('',#1554,1.);
#1556=CARTESIAN_POINT('',(22.1361,19.1389,-12.7));
#1557=LINE('',#1556,#1555);
#1558=CARTESIAN_POINT('',(22.1361,-19.1389,-12.7));
#1559=VERTEX_POINT('',#1558);
#1560=EDGE_CURVE('E1453',#1559,#1551,#1557,.T.);
#1561=ORIENTED_EDGE('',*,*,#1560,.F.);
#1562=DIRECTION('',(-1.,0.,0.));
#1563=VECTOR('',#1562,1.);
#1564=CARTESIAN_POINT('',(22.1361,-19.1389,-12.7));
#1565=LINE('',#1564,#1563);
#1566=CARTESIAN_POINT('',(25.9860285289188,-19.1389,-12.7));
#1567=VERTEX_POINT('',#1566);
#1568=EDGE_CURVE('E1450',#1567,#1559,#1565,.T.);
#1569=ORIENTED_EDGE('',*,*,#1568,.F.);
#1570=CARTESIAN_POINT('',(29.337,-22.1361,-12.7));
#1571=DIRECTION('',(0.,0.,1.));
#1572=DIRECTION('',(1.,0.,0.));
#1573=AXIS2_PLACEMENT_3D('',#1570,#1571,#1572);
#1574=CIRCLE('',#1573,4.4958);
#1575=CARTESIAN_POINT('',(32.6879714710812,-19.1389,-12.7));
#1576=VERTEX_POINT('',#1575);
#1577=EDGE_CURVE('E1447',#1576,#1567,#1574,.T.);
#1578=ORIENTED_EDGE('',*,*,#1577,.F.);
#1579=DIRECTION('',(-1.,0.,0.));
#1580=VECTOR('',#1579,1.);
#1581=CARTESIAN_POINT('',(32.6879714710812,-19.1389,-12.7));
#1582=LINE('',#1581,#1580);
#1583=CARTESIAN_POINT('',(39.7764,-19.1389,-12.7));
#1584=VERTEX_POINT('',#1583);
#1585=EDGE_CURVE('E1444',#1584,#1576,#1582,.T.);
#1586=ORIENTED_EDGE('',*,*,#1585,.F.);
#1587=DIRECTION('',(0.,-1.,0.));
#1588=VECTOR('',#1587,1.);
#1589=CARTESIAN_POINT('',(39.7764,-19.1389,-12.7));
#1590=LINE('',#1589,#1588);
#1591=CARTESIAN_POINT('',(39.7764,-12.6111,-12.7));
#1592=VERTEX_POINT('',#1591);
#1593=EDGE_CURVE('E1441',#1592,#1584,#1590,.T.);
#1594=ORIENTED_EDGE('',*,*,#1593,.F.);
#1595=DIRECTION('',(1.,0.,0.));
#1596=VECTOR('',#1595,1.);
#1597=CARTESIAN_POINT('',(39.7764,-12.6111,-12.7));
#1598=LINE('',#1597,#1596);
#1599=CARTESIAN_POINT('',(34.925,-12.6111,-12.7));
#1600=VERTEX_POINT('',#1599);
#1601=EDGE_CURVE('E1438',#1600,#1592,#1598,.T.);
#1602=ORIENTED_EDGE('',*,*,#1601,.F.);
#1603=DIRECTION('',(0.,-1.,0.));
#1604=VECTOR('',#1603,1.);
#1605=CARTESIAN_POINT('',(34.925,-11.1125,-12.7));
#1606=LINE('',#1605,#1604);
#1607=CARTESIAN_POINT('',(34.925,-11.1125,-12.7));
#1608=VERTEX_POINT('',#1607);
#1609=EDGE_CURVE('E1435',#1608,#1600,#1606,.T.);
#1610=ORIENTED_EDGE('',*,*,#1609,.F.);
#1611=DIRECTION('',(-1.,0.,0.));
#1612=VECTOR('',#1611,1.);
#1613=CARTESIAN_POINT('',(39.7764,-11.1125,-12.7));
#1614=LINE('',#1613,#1612);
#1615=CARTESIAN_POINT('',(39.7764,-11.1125,-12.7));
#1616=VERTEX_POINT('',#1615);
#1617=EDGE_CURVE('E1432',#1616,#1608,#1614,.T.);
#1618=ORIENTED_EDGE('',*,*,#1617,.F.);
#1619=CARTESIAN_POINT('',(39.7764,-12.6111,-12.7));
#1620=DIRECTION('',(0.,0.,1.));
#1621=DIRECTION('',(-1.,0.,0.));
#1622=AXIS2_PLACEMENT_3D('',#1619,#1620,#1621);
#1623=CIRCLE('',#1622,1.49859999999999);
#1624=CARTESIAN_POINT('',(41.275,-12.6111,-12.7));
#1625=VERTEX_POINT('',#1624);
#1626=EDGE_CURVE('E1429',#1625,#1616,#1623,.T.);
#1627=ORIENTED_EDGE('',*,*,#1626,.F.);
#1628=DIRECTION('',(0.,1.,0.));
#1629=VECTOR('',#1628,1.);
#1630=CARTESIAN_POINT('',(41.275,-19.1389,-12.7));
#1631=LINE('',#1630,#1629);
#1632=CARTESIAN_POINT('',(41.275,-19.1389,-12.7));
#1633=VERTEX_POINT('',#1632);
#1634=EDGE_CURVE('E1426',#1633,#1625,#1631,.T.);
#1635=ORIENTED_EDGE('',*,*,#1634,.F.);
#1636=CARTESIAN_POINT('',(39.7764,-19.1389,-12.7));
#1637=DIRECTION('',(0.,0.,1.));
#1638=DIRECTION('',(-1.,0.,0.));
#1639=AXIS2_PLACEMENT_3D('',#1636,#1637,#1638);
#1640=CIRCLE('',#1639,1.4986);
#1641=CARTESIAN_POINT('',(39.7764,-20.6375,-12.7));
#1642=VERTEX_POINT('',#1641);
#1643=EDGE_CURVE('E1423',#1642,#1633,#1640,.T.);
#1644=ORIENTED_EDGE('',*,*,#1643,.F.);
#1645=DIRECTION('',(1.,0.,0.));
#1646=VECTOR('',#1645,1.);
#1647=CARTESIAN_POINT('',(31.9326513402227,-20.6375,-12.7));
#1648=LINE('',#1647,#1646);
#1649=CARTESIAN_POINT('',(31.9326513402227,-20.6375,-12.7));
#1650=VERTEX_POINT('',#1649);
#1651=EDGE_CURVE('E1420',#1650,#1642,#1648,.T.);
#1652=ORIENTED_EDGE('',*,*,#1651,.F.);
#1653=CARTESIAN_POINT('',(29.337,-22.1361,-12.7));
#1654=DIRECTION('',(0.,0.,-1.));
#1655=DIRECTION('',(1.,0.,0.));
#1656=AXIS2_PLACEMENT_3D('',#1653,#1654,#1655);
#1657=CIRCLE('',#1656,2.9972);
#1658=CARTESIAN_POINT('',(26.7413486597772,-20.6375,-12.7));
#1659=VERTEX_POINT('',#1658);
#1660=EDGE_CURVE('E1417',#1659,#1650,#1657,.T.);
#1661=ORIENTED_EDGE('',*,*,#1660,.F.);
#1662=DIRECTION('',(1.,0.,0.));
#1663=VECTOR('',#1662,1.);
#1664=CARTESIAN_POINT('',(22.1361,-20.6375,-12.7));
#1665=LINE('',#1664,#1663);
#1666=CARTESIAN_POINT('',(22.1361,-20.6375,-12.7));
#1667=VERTEX_POINT('',#1666);
#1668=EDGE_CURVE('E1414',#1667,#1659,#1665,.T.);
#1669=ORIENTED_EDGE('',*,*,#1668,.F.);
#1670=CARTESIAN_POINT('',(22.1361,-19.1389,-12.7));
#1671=DIRECTION('',(0.,0.,1.));
#1672=DIRECTION('',(-1.,0.,0.));
#1673=AXIS2_PLACEMENT_3D('',#1670,#1671,#1672);
#1674=CIRCLE('',#1673,1.4986);
#1675=CARTESIAN_POINT('',(20.6375,-19.1389,-12.7));
#1676=VERTEX_POINT('',#1675);
#1677=EDGE_CURVE('E1411',#1676,#1667,#1674,.T.);
#1678=ORIENTED_EDGE('',*,*,#1677,.F.);
#1679=CARTESIAN_POINT('',(19.1389,-19.1389,-12.7));
#1680=DIRECTION('',(0.,0.,-1.));
#1681=DIRECTION('',(-1.,0.,0.));
#1682=AXIS2_PLACEMENT_3D('',#1679,#1680,#1681);
#1683=CIRCLE('',#1682,1.4986);
#1684=CARTESIAN_POINT('',(19.1389,-20.6375,-12.7));
#1685=VERTEX_POINT('',#1684);
#1686=EDGE_CURVE('E1658',#1676,#1685,#1683,.T.);
#1687=ORIENTED_EDGE('',*,*,#1686,.T.);
#1688=DIRECTION('',(-1.,0.,0.));
#1689=VECTOR('',#1688,1.);
#1690=CARTESIAN_POINT('',(19.1389,-20.6375,-12.7));
#1691=LINE('',#1690,#1689);
#1692=CARTESIAN_POINT('',(12.6111,-20.6375,-12.7));
#1693=VERTEX_POINT('',#1692);
#1694=EDGE_CURVE('E1655',#1685,#1693,#1691,.T.);
#1695=ORIENTED_EDGE('',*,*,#1694,.T.);
#1696=CARTESIAN_POINT('',(12.6111,-19.1389,-12.7));
#1697=DIRECTION('',(0.,0.,-1.));
#1698=DIRECTION('',(-1.,0.,0.));
#1699=AXIS2_PLACEMENT_3D('',#1696,#1697,#1698);
#1700=CIRCLE('',#1699,1.4986);
#1701=CARTESIAN_POINT('',(11.1125,-19.1389,-12.7));
#1702=VERTEX_POINT('',#1701);
#1703=EDGE_CURVE('E1652',#1693,#1702,#1700,.T.);
#1704=ORIENTED_EDGE('',*,*,#1703,.T.);
#1705=DIRECTION('',(0.,1.,0.));
#1706=VECTOR('',#1705,1.);
#1707=CARTESIAN_POINT('',(11.1125,-19.1389,-12.7));
#1708=LINE('',#1707,#1706);
#1709=CARTESIAN_POINT('',(11.1125,-14.2875,-12.7));
#1710=VERTEX_POINT('',#1709);
#1711=EDGE_CURVE('E1649',#1702,#1710,#1708,.T.);
#1712=ORIENTED_EDGE('',*,*,#1711,.T.);
#1713=DIRECTION('',(1.,0.,0.));
#1714=VECTOR('',#1713,1.);
#1715=CARTESIAN_POINT('',(11.1125,-14.2875,-12.7));
#1716=LINE('',#1715,#1714);
#1717=CARTESIAN_POINT('',(12.6111,-14.2875,-12.7));
#1718=VERTEX_POINT('',#1717);
#1719=EDGE_CURVE('E1646',#1710,#1718,#1716,.T.);
#1720=ORIENTED_EDGE('',*,*,#1719,.T.);
#1721=DIRECTION('',(0.,-1.,0.));
#1722=VECTOR('',#1721,1.);
#1723=CARTESIAN_POINT('',(12.6111,-19.1389,-12.7));
#1724=LINE('',#1723,#1722);
#1725=CARTESIAN_POINT('',(12.6111,-19.1389,-12.7));
#1726=VERTEX_POINT('',#1725);
#1727=EDGE_CURVE('E1643',#1718,#1726,#1724,.T.);
#1728=ORIENTED_EDGE('',*,*,#1727,.T.);
#1729=DIRECTION('',(1.,0.,0.));
#1730=VECTOR('',#1729,1.);
#1731=CARTESIAN_POINT('',(19.1389,-19.1389,-12.7));
#1732=LINE('',#1731,#1730);
#1733=CARTESIAN_POINT('',(19.1389,-19.1389,-12.7));
#1734=VERTEX_POINT('',#1733);
#1735=EDGE_CURVE('E1640',#1726,#1734,#1732,.T.);
#1736=ORIENTED_EDGE('',*,*,#1735,.T.);
#1737=DIRECTION('',(0.,1.,0.));
#1738=VECTOR('',#1737,1.);
#1739=CARTESIAN_POINT('',(19.1389,-12.0504714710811,-12.7));
#1740=LINE('',#1739,#1738);
#1741=CARTESIAN_POINT('',(19.1389,-12.0504714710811,-12.7));
#1742=VERTEX_POINT('',#1741);
#1743=EDGE_CURVE('E1637',#1734,#1742,#1740,.T.);
#1744=ORIENTED_EDGE('',*,*,#1743,.T.);
#1745=CARTESIAN_POINT('',(22.1361,-8.69949999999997,-12.7));
#1746=DIRECTION('',(0.,0.,-1.));
#1747=DIRECTION('',(1.,0.,0.));
#1748=AXIS2_PLACEMENT_3D('',#1745,#1746,#1747);
#1749=CIRCLE('',#1748,4.4958);
#1750=CARTESIAN_POINT('',(19.1389,-5.34852852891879,-12.7));
#1751=VERTEX_POINT('',#1750);
#1752=EDGE_CURVE('E1634',#1742,#1751,#1749,.T.);
#1753=ORIENTED_EDGE('',*,*,#1752,.T.);
#1754=DIRECTION('',(0.,1.,0.));
#1755=VECTOR('',#1754,1.);
#1756=CARTESIAN_POINT('',(19.1389,-1.49860000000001,-12.7));
#1757=LINE('',#1756,#1755);
#1758=CARTESIAN_POINT('',(19.1389,-1.49860000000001,-12.7));
#1759=VERTEX_POINT('',#1758);
#1760=EDGE_CURVE('E1631',#1751,#1759,#1757,.T.);
#1761=ORIENTED_EDGE('',*,*,#1760,.T.);
#1762=DIRECTION('',(-1.,0.,0.));
#1763=VECTOR('',#1762,1.);
#1764=CARTESIAN_POINT('',(-19.1389,-1.4986,-12.7));
#1765=LINE('',#1764,#1763);
#1766=CARTESIAN_POINT('',(-19.1389,-1.4986,-12.7));
#1767=VERTEX_POINT('',#1766);
#1768=EDGE_CURVE('E1628',#1759,#1767,#1765,.T.);
#1769=ORIENTED_EDGE('',*,*,#1768,.T.);
#1770=DIRECTION('',(0.,-1.,0.));
#1771=VECTOR('',#1770,1.);
#1772=CARTESIAN_POINT('',(-19.1389,-5.34852852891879,-12.7));
#1773=LINE('',#1772,#1771);
#1774=CARTESIAN_POINT('',(-19.1389,-5.34852852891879,-12.7));
#1775=VERTEX_POINT('',#1774);
#1776=EDGE_CURVE('E1625',#1767,#1775,#1773,.T.);
#1777=ORIENTED_EDGE('',*,*,#1776,.T.);
#1778=CARTESIAN_POINT('',(-22.1361,-8.69949999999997,-12.7));
#1779=DIRECTION('',(0.,0.,-1.));
#1780=DIRECTION('',(1.,0.,0.));
#1781=AXIS2_PLACEMENT_3D('',#1778,#1779,#1780);
#1782=CIRCLE('',#1781,4.4958);
#1783=CARTESIAN_POINT('',(-19.1389,-12.0504714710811,-12.7));
#1784=VERTEX_POINT('',#1783);
#1785=EDGE_CURVE('E1622',#1775,#1784,#1782,.T.);
#1786=ORIENTED_EDGE('',*,*,#1785,.T.);
#1787=DIRECTION('',(0.,-1.,0.));
#1788=VECTOR('',#1787,1.);
#1789=CARTESIAN_POINT('',(-19.1389,-19.1389,-12.7));
#1790=LINE('',#1789,#1788);
#1791=CARTESIAN_POINT('',(-19.1389,-19.1389,-12.7));
#1792=VERTEX_POINT('',#1791);
#1793=EDGE_CURVE('E1536',#1784,#1792,#1790,.T.);
#1794=ORIENTED_EDGE('',*,*,#1793,.T.);
#1795=DIRECTION('',(1.,0.,0.));
#1796=VECTOR('',#1795,1.);
#1797=CARTESIAN_POINT('',(-19.1389,-19.1389,-12.7));
#1798=LINE('',#1797,#1796);
#1799=CARTESIAN_POINT('',(-12.6111,-19.1389,-12.7));
#1800=VERTEX_POINT('',#1799);
#1801=EDGE_CURVE('E1541',#1792,#1800,#1798,.T.);
#1802=ORIENTED_EDGE('',*,*,#1801,.T.);
#1803=DIRECTION('',(0.,1.,0.));
#1804=VECTOR('',#1803,1.);
#1805=CARTESIAN_POINT('',(-12.6111,-19.1389,-12.7));
#1806=LINE('',#1805,#1804);
#1807=CARTESIAN_POINT('',(-12.6111,-14.2875,-12.7));
#1808=VERTEX_POINT('',#1807);
#1809=EDGE_CURVE('E1694',#1800,#1808,#1806,.T.);
#1810=ORIENTED_EDGE('',*,*,#1809,.T.);
#1811=DIRECTION('',(1.,0.,0.));
#1812=VECTOR('',#1811,1.);
#1813=CARTESIAN_POINT('',(-12.6111,-14.2875,-12.7));
#1814=LINE('',#1813,#1812);
#1815=CARTESIAN_POINT('',(-11.1125,-14.2875,-12.7));
#1816=VERTEX_POINT('',#1815);
#1817=EDGE_CURVE('E1691',#1808,#1816,#1814,.T.);
#1818=ORIENTED_EDGE('',*,*,#1817,.T.);
#1819=DIRECTION('',(0.,-1.,0.));
#1820=VECTOR('',#1819,1.);
#1821=CARTESIAN_POINT('',(-11.1125,-19.1389,-12.7));
#1822=LINE('',#1821,#1820);
#1823=CARTESIAN_POINT('',(-11.1125,-19.1389,-12.7));
#1824=VERTEX_POINT('',#1823);
#1825=EDGE_CURVE('E1688',#1816,#1824,#1822,.T.);
#1826=ORIENTED_EDGE('',*,*,#1825,.T.);
#1827=CARTESIAN_POINT('',(-12.6111,-19.1389,-12.7));
#1828=DIRECTION('',(0.,0.,-1.));
#1829=DIRECTION('',(-1.,0.,0.));
#1830=AXIS2_PLACEMENT_3D('',#1827,#1828,#1829);
#1831=CIRCLE('',#1830,1.4986);
#1832=CARTESIAN_POINT('',(-12.6111,-20.6375,-12.7));
#1833=VERTEX_POINT('',#1832);
#1834=EDGE_CURVE('E1685',#1824,#1833,#1831,.T.);
#1835=ORIENTED_EDGE('',*,*,#1834,.T.);
#1836=DIRECTION('',(-1.,0.,0.));
#1837=VECTOR('',#1836,1.);
#1838=CARTESIAN_POINT('',(-19.1389,-20.6375,-12.7));
#1839=LINE('',#1838,#1837);
#1840=CARTESIAN_POINT('',(-19.1389,-20.6375,-12.7));
#1841=VERTEX_POINT('',#1840);
#1842=EDGE_CURVE('E1682',#1833,#1841,#1839,.T.);
#1843=ORIENTED_EDGE('',*,*,#1842,.T.);
#1844=CARTESIAN_POINT('',(-19.1389,-19.1389,-12.7));
#1845=DIRECTION('',(0.,0.,-1.));
#1846=DIRECTION('',(-1.,0.,0.));
#1847=AXIS2_PLACEMENT_3D('',#1844,#1845,#1846);
#1848=CIRCLE('',#1847,1.4986);
#1849=CARTESIAN_POINT('',(-20.6375,-19.1389,-12.7));
#1850=VERTEX_POINT('',#1849);
#1851=EDGE_CURVE('E1679',#1841,#1850,#1848,.T.);
#1852=ORIENTED_EDGE('',*,*,#1851,.T.);
#1853=DIRECTION('',(0.,1.,0.));
#1854=VECTOR('',#1853,1.);
#1855=CARTESIAN_POINT('',(-20.6375,-19.1389,-12.7));
#1856=LINE('',#1855,#1854);
#1857=CARTESIAN_POINT('',(-20.6375,-11.2951513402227,-12.7));
#1858=VERTEX_POINT('',#1857);
#1859=EDGE_CURVE('E1676',#1850,#1858,#1856,.T.);
#1860=ORIENTED_EDGE('',*,*,#1859,.T.);
#1861=CARTESIAN_POINT('',(-22.1361,-8.69949999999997,-12.7));
#1862=DIRECTION('',(0.,0.,1.));
#1863=DIRECTION('',(1.,0.,0.));
#1864=AXIS2_PLACEMENT_3D('',#1861,#1862,#1863);
#1865=CIRCLE('',#1864,2.9972);
#1866=CARTESIAN_POINT('',(-20.6375,-6.10384865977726,-12.7));
#1867=VERTEX_POINT('',#1866);
#1868=EDGE_CURVE('E1673',#1858,#1867,#1865,.T.);
#1869=ORIENTED_EDGE('',*,*,#1868,.T.);
#1870=DIRECTION('',(0.,1.,0.));
#1871=VECTOR('',#1870,1.);
#1872=CARTESIAN_POINT('',(-20.6375,-6.10384865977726,-12.7));
#1873=LINE('',#1872,#1871);
#1874=CARTESIAN_POINT('',(-20.6375,-1.4986,-12.7));
#1875=VERTEX_POINT('',#1874);
#1876=EDGE_CURVE('E1670',#1867,#1875,#1873,.T.);
#1877=ORIENTED_EDGE('',*,*,#1876,.T.);
#1878=CARTESIAN_POINT('',(-19.1389,-1.4986,-12.7));
#1879=DIRECTION('',(0.,0.,-1.));
#1880=DIRECTION('',(-1.,0.,0.));
#1881=AXIS2_PLACEMENT_3D('',#1878,#1879,#1880);
#1882=CIRCLE('',#1881,1.4986);
#1883=EDGE_CURVE('E1667',#1875,#386,#1882,.T.);
#1884=ORIENTED_EDGE('',*,*,#1883,.T.);
#1885=ORIENTED_EDGE('',*,*,#387,.F.);
#1886=ORIENTED_EDGE('',*,*,#355,.F.);
#1887=ORIENTED_EDGE('',*,*,#323,.F.);
#1888=ORIENTED_EDGE('',*,*,#291,.F.);
#1889=ORIENTED_EDGE('',*,*,#259,.F.);
#1890=ORIENTED_EDGE('',*,*,#227,.F.);
#1891=ORIENTED_EDGE('',*,*,#195,.F.);
#1892=ORIENTED_EDGE('',*,*,#163,.F.);
#1893=ORIENTED_EDGE('',*,*,#132,.F.);
#1894=ORIENTED_EDGE('',*,*,#101,.F.);
#1895=ORIENTED_EDGE('',*,*,#70,.F.);
#1896=ORIENTED_EDGE('',*,*,#32,.F.);
#1897=ORIENTED_EDGE('',*,*,#889,.F.);
#1898=ORIENTED_EDGE('',*,*,#859,.F.);
#1899=ORIENTED_EDGE('',*,*,#828,.F.);
#1900=ORIENTED_EDGE('',*,*,#797,.F.);
#1901=ORIENTED_EDGE('',*,*,#765,.F.);
#1902=ORIENTED_EDGE('',*,*,#733,.F.);
#1903=ORIENTED_EDGE('',*,*,#702,.F.);
#1904=ORIENTED_EDGE('',*,*,#671,.F.);
#1905=ORIENTED_EDGE('',*,*,#640,.F.);
#1906=ORIENTED_EDGE('',*,*,#609,.F.);
#1907=ORIENTED_EDGE('',*,*,#577,.F.);
#1908=ORIENTED_EDGE('',*,*,#545,.F.);
#1909=EDGE_LOOP('',(#1436,#1445,#1453,#1462,#1470,#1479,#1487,#1496,#1504,#1512,#1520,#1528,
#1536,#1545,#1553,#1561,#1569,#1578,#1586,#1594,#1602,#1610,#1618,#1627,#1635,#1644,#1652,#1661,
#1669,#1678,#1687,#1695,#1704,#1712,#1720,#1728,#1736,#1744,#1753,#1761,#1769,#1777,#1786,#1794,
#1802,#1810,#1818,#1826,#1835,#1843,#1852,#1860,#1869,#1877,#1884,#1885,#1886,#1887,#1888,#1889,
#1890,#1891,#1892,#1893,#1894,#1895,#1896,#1897,#1898,#1899,#1900,#1901,#1902,#1903,#1904,#1905,
#1906,#1907,#1908));
#1910=FACE_BOUND('',#1909,.T.);
#1911=CARTESIAN_POINT('',(20.6375,-1.49860000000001,-12.7));
#1912=VERTEX_POINT('',#1911);
#1913=EDGE_CURVE('E1409',#421,#1912,#1431,.T.);
#1914=ORIENTED_EDGE('',*,*,#1913,.F.);
#1915=ORIENTED_EDGE('',*,*,#422,.F.);
#1916=CARTESIAN_POINT('',(19.1389,-1.49860000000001,-12.7));
#1917=DIRECTION('',(0.,0.,-1.));
#1918=DIRECTION('',(-1.,0.,0.));
#1919=AXIS2_PLACEMENT_3D('',#1916,#1917,#1918);
#1920=CIRCLE('',#1919,1.4986);
#1921=EDGE_CURVE('E1664',#419,#1912,#1920,.T.);
#1922=ORIENTED_EDGE('',*,*,#1921,.T.);
#1923=EDGE_LOOP('',(#1914,#1915,#1922));
#1924=FACE_BOUND('',#1923,.T.);
#1925=CARTESIAN_POINT('',(22.1361,-8.69949999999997,-12.7));
#1926=DIRECTION('',(0.,0.,1.));
#1927=DIRECTION('',(1.,0.,0.));
#1928=AXIS2_PLACEMENT_3D('',#1925,#1926,#1927);
#1929=CIRCLE('',#1928,2.9972);
#1930=CARTESIAN_POINT('',(20.6375,-6.10384865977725,-12.7));
#1931=VERTEX_POINT('',#1930);
#1932=CARTESIAN_POINT('',(20.6375,-11.2951513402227,-12.7));
#1933=VERTEX_POINT('',#1932);
#1934=EDGE_CURVE('E1661',#1931,#1933,#1929,.T.);
#1935=ORIENTED_EDGE('',*,*,#1934,.T.);
#1936=EDGE_CURVE('E1406',#1931,#1933,#1431,.T.);
#1937=ORIENTED_EDGE('',*,*,#1936,.F.);
#1938=EDGE_LOOP('',(#1935,#1937));
#1939=FACE_BOUND('',#1938,.T.);
#1940=ADVANCED_FACE('F402',(#1435,#1910,#1924,#1939),#1426,.F.);
#1941=CARTESIAN_POINT('',(-19.1389,-19.1389,12.7));
#1942=DIRECTION('',(1.,0.,0.));
#1943=DIRECTION('',(0.,0.,-1.));
#1944=AXIS2_PLACEMENT_3D('',#1941,#1942,#1943);
#1945=PLANE('',#1944);
#1946=ORIENTED_EDGE('',*,*,#1793,.F.);
#1947=DIRECTION('',(0.,0.,-1.));
#1948=VECTOR('',#1947,1.);
#1949=CARTESIAN_POINT('',(-19.1389,-12.0504714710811,12.7));
#1950=LINE('',#1949,#1948);
#1951=EDGE_CURVE('E268',#1048,#1784,#1950,.T.);
#1952=ORIENTED_EDGE('',*,*,#1951,.F.);
#1953=ORIENTED_EDGE('',*,*,#1049,.T.);
#1954=DIRECTION('',(0.,0.,-1.));
#1955=VECTOR('',#1954,1.);
#1956=CARTESIAN_POINT('',(-19.1389,-19.1389,12.7));
#1957=LINE('',#1956,#1955);
#1958=EDGE_CURVE('E1619',#1040,#1792,#1957,.T.);
#1959=ORIENTED_EDGE('',*,*,#1958,.T.);
#1960=EDGE_LOOP('',(#1946,#1952,#1953,#1959));
#1961=FACE_BOUND('',#1960,.T.);
#1962=ADVANCED_FACE('F600',(#1961),#1945,.T.);
#1963=CARTESIAN_POINT('',(-22.1361,-8.69949999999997,12.7));
#1964=DIRECTION('',(0.,0.,-1.));
#1965=DIRECTION('',(-1.,0.,0.));
#1966=AXIS2_PLACEMENT_3D('',#1963,#1964,#1965);
#1967=CYLINDRICAL_SURFACE('',#1966,4.4958);
#1968=ORIENTED_EDGE('',*,*,#1785,.F.);
#1969=DIRECTION('',(0.,0.,-1.));
#1970=VECTOR('',#1969,1.);
#1971=CARTESIAN_POINT('',(-19.1389,-5.34852852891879,12.7));
#1972=LINE('',#1971,#1970);
#1973=EDGE_CURVE('E1776',#1057,#1775,#1972,.T.);
#1974=ORIENTED_EDGE('',*,*,#1973,.F.);
#1975=ORIENTED_EDGE('',*,*,#1058,.T.);
#1976=ORIENTED_EDGE('',*,*,#1951,.T.);
#1977=EDGE_LOOP('',(#1968,#1974,#1975,#1976));
#1978=FACE_BOUND('',#1977,.T.);
#1979=ADVANCED_FACE('F615',(#1978),#1967,.T.);
#1980=CARTESIAN_POINT('',(-19.1389,-5.34852852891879,12.7));
#1981=DIRECTION('',(1.,0.,0.));
#1982=DIRECTION('',(0.,1.,0.));
#1983=AXIS2_PLACEMENT_3D('',#1980,#1981,#1982);
#1984=PLANE('',#1983);
#1985=ORIENTED_EDGE('',*,*,#1776,.F.);
#1986=DIRECTION('',(0.,0.,-1.));
#1987=VECTOR('',#1986,1.);
#1988=CARTESIAN_POINT('',(-19.1389,-1.4986,12.7));
#1989=LINE('',#1988,#1987);
#1990=EDGE_CURVE('E1773',#1065,#1767,#1989,.T.);
#1991=ORIENTED_EDGE('',*,*,#1990,.F.);
#1992=ORIENTED_EDGE('',*,*,#1066,.T.);
#1993=ORIENTED_EDGE('',*,*,#1973,.T.);
#1994=EDGE_LOOP('',(#1985,#1991,#1992,#1993));
#1995=FACE_BOUND('',#1994,.T.);
#1996=ADVANCED_FACE('F625',(#1995),#1984,.T.);
#1997=CARTESIAN_POINT('',(-19.1389,-1.4986,12.7));
#1998=DIRECTION('',(0.,-1.,0.));
#1999=DIRECTION('',(1.,0.,0.));
#2000=AXIS2_PLACEMENT_3D('',#1997,#1998,#1999);
#2001=PLANE('',#2000);
#2002=ORIENTED_EDGE('',*,*,#1768,.F.);
#2003=DIRECTION('',(0.,0.,-1.));
#2004=VECTOR('',#2003,1.);
#2005=CARTESIAN_POINT('',(19.1389,-1.49860000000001,12.7));
#2006=LINE('',#2005,#2004);
#2007=EDGE_CURVE('E1770',#1073,#1759,#2006,.T.);
#2008=ORIENTED_EDGE('',*,*,#2007,.F.);
#2009=ORIENTED_EDGE('',*,*,#1074,.T.);
#2010=ORIENTED_EDGE('',*,*,#1990,.T.);
#2011=EDGE_LOOP('',(#2002,#2008,#2009,#2010));
#2012=FACE_BOUND('',#2011,.T.);
#2013=ADVANCED_FACE('F635',(#2012),#2001,.T.);
#2014=CARTESIAN_POINT('',(19.1389,-1.49860000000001,12.7));
#2015=DIRECTION('',(-1.,0.,0.));
#2016=DIRECTION('',(0.,0.,1.));
#2017=AXIS2_PLACEMENT_3D('',#2014,#2015,#2016);
#2018=PLANE('',#2017);
#2019=ORIENTED_EDGE('',*,*,#1760,.F.);
#2020=DIRECTION('',(0.,0.,-1.));
#2021=VECTOR('',#2020,1.);
#2022=CARTESIAN_POINT('',(19.1389,-5.34852852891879,12.7));
#2023=LINE('',#2022,#2021);
#2024=EDGE_CURVE('E1767',#1081,#1751,#2023,.T.);
#2025=ORIENTED_EDGE('',*,*,#2024,.F.);
#2026=ORIENTED_EDGE('',*,*,#1082,.T.);
#2027=ORIENTED_EDGE('',*,*,#2007,.T.);
#2028=EDGE_LOOP('',(#2019,#2025,#2026,#2027));
#2029=FACE_BOUND('',#2028,.T.);
#2030=ADVANCED_FACE('F645',(#2029),#2018,.T.);
#2031=CARTESIAN_POINT('',(22.1361,-8.69949999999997,12.7));
#2032=DIRECTION('',(0.,0.,-1.));
#2033=DIRECTION('',(-1.,0.,0.));
#2034=AXIS2_PLACEMENT_3D('',#2031,#2032,#2033);
#2035=CYLINDRICAL_SURFACE('',#2034,4.4958);
#2036=ORIENTED_EDGE('',*,*,#1752,.F.);
#2037=DIRECTION('',(0.,0.,-1.));
#2038=VECTOR('',#2037,1.);
#2039=CARTESIAN_POINT('',(19.1389,-12.0504714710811,12.7));
#2040=LINE('',#2039,#2038);
#2041=EDGE_CURVE('E1764',#1090,#1742,#2040,.T.);
#2042=ORIENTED_EDGE('',*,*,#2041,.F.);
#2043=ORIENTED_EDGE('',*,*,#1091,.T.);
#2044=ORIENTED_EDGE('',*,*,#2024,.T.);
#2045=EDGE_LOOP('',(#2036,#2042,#2043,#2044));
#2046=FACE_BOUND('',#2045,.T.);
#2047=ADVANCED_FACE('F655',(#2046),#2035,.T.);
#2048=CARTESIAN_POINT('',(19.1389,-12.0504714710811,12.7));
#2049=DIRECTION('',(-1.,0.,0.));
#2050=DIRECTION('',(0.,0.,1.));
#2051=AXIS2_PLACEMENT_3D('',#2048,#2049,#2050);
#2052=PLANE('',#2051);
#2053=ORIENTED_EDGE('',*,*,#1743,.F.);
#2054=DIRECTION('',(0.,0.,-1.));
#2055=VECTOR('',#2054,1.);
#2056=CARTESIAN_POINT('',(19.1389,-19.1389,12.7));
#2057=LINE('',#2056,#2055);
#2058=EDGE_CURVE('E1761',#1098,#1734,#2057,.T.);
#2059=ORIENTED_EDGE('',*,*,#2058,.F.);
#2060=ORIENTED_EDGE('',*,*,#1099,.T.);
#2061=ORIENTED_EDGE('',*,*,#2041,.T.);
#2062=EDGE_LOOP('',(#2053,#2059,#2060,#2061));
#2063=FACE_BOUND('',#2062,.T.);
#2064=ADVANCED_FACE('F665',(#2063),#2052,.T.);
#2065=CARTESIAN_POINT('',(19.1389,-19.1389,12.7));
#2066=DIRECTION('',(0.,1.,0.));
#2067=DIRECTION('',(-1.,0.,0.));
#2068=AXIS2_PLACEMENT_3D('',#2065,#2066,#2067);
#2069=PLANE('',#2068);
#2070=ORIENTED_EDGE('',*,*,#1735,.F.);
#2071=DIRECTION('',(0.,0.,-1.));
#2072=VECTOR('',#2071,1.);
#2073=CARTESIAN_POINT('',(12.6111,-19.1389,12.7));
#2074=LINE('',#2073,#2072);
#2075=EDGE_CURVE('E1758',#1106,#1726,#2074,.T.);
#2076=ORIENTED_EDGE('',*,*,#2075,.F.);
#2077=ORIENTED_EDGE('',*,*,#1107,.T.);
#2078=ORIENTED_EDGE('',*,*,#2058,.T.);
#2079=EDGE_LOOP('',(#2070,#2076,#2077,#2078));
#2080=FACE_BOUND('',#2079,.T.);
#2081=ADVANCED_FACE('F675',(#2080),#2069,.T.);
#2082=CARTESIAN_POINT('',(12.6111,-19.1389,12.7));
#2083=DIRECTION('',(1.,0.,0.));
#2084=DIRECTION('',(0.,0.,-1.));
#2085=AXIS2_PLACEMENT_3D('',#2082,#2083,#2084);
#2086=PLANE('',#2085);
#2087=ORIENTED_EDGE('',*,*,#1727,.F.);
#2088=DIRECTION('',(0.,0.,-1.));
#2089=VECTOR('',#2088,1.);
#2090=CARTESIAN_POINT('',(12.6111,-14.2875,12.7));
#2091=LINE('',#2090,#2089);
#2092=EDGE_CURVE('E1755',#1114,#1718,#2091,.T.);
#2093=ORIENTED_EDGE('',*,*,#2092,.F.);
#2094=ORIENTED_EDGE('',*,*,#1115,.T.);
#2095=ORIENTED_EDGE('',*,*,#2075,.T.);
#2096=EDGE_LOOP('',(#2087,#2093,#2094,#2095));
#2097=FACE_BOUND('',#2096,.T.);
#2098=ADVANCED_FACE('F685',(#2097),#2086,.T.);
#2099=CARTESIAN_POINT('',(11.1125,-14.2875,12.7));
#2100=DIRECTION('',(0.,1.,0.));
#2101=DIRECTION('',(0.,0.,1.));
#2102=AXIS2_PLACEMENT_3D('',#2099,#2100,#2101);
#2103=PLANE('',#2102);
#2104=ORIENTED_EDGE('',*,*,#1719,.F.);
#2105=DIRECTION('',(0.,0.,-1.));
#2106=VECTOR('',#2105,1.);
#2107=CARTESIAN_POINT('',(11.1125,-14.2875,12.7));
#2108=LINE('',#2107,#2106);
#2109=EDGE_CURVE('E1752',#1122,#1710,#2108,.T.);
#2110=ORIENTED_EDGE('',*,*,#2109,.F.);
#2111=ORIENTED_EDGE('',*,*,#1123,.T.);
#2112=ORIENTED_EDGE('',*,*,#2092,.T.);
#2113=EDGE_LOOP('',(#2104,#2110,#2111,#2112));
#2114=FACE_BOUND('',#2113,.T.);
#2115=ADVANCED_FACE('F695',(#2114),#2103,.T.);
#2116=CARTESIAN_POINT('',(11.1125,-19.1389,12.7));
#2117=DIRECTION('',(-1.,0.,0.));
#2118=DIRECTION('',(0.,-1.,0.));
#2119=AXIS2_PLACEMENT_3D('',#2116,#2117,#2118);
#2120=PLANE('',#2119);
#2121=ORIENTED_EDGE('',*,*,#1711,.F.);
#2122=DIRECTION('',(0.,0.,-1.));
#2123=VECTOR('',#2122,1.);
#2124=CARTESIAN_POINT('',(11.1125,-19.1389,12.7));
#2125=LINE('',#2124,#2123);
#2126=EDGE_CURVE('E1749',#1130,#1702,#2125,.T.);
#2127=ORIENTED_EDGE('',*,*,#2126,.F.);
#2128=ORIENTED_EDGE('',*,*,#1131,.T.);
#2129=ORIENTED_EDGE('',*,*,#2109,.T.);
#2130=EDGE_LOOP('',(#2121,#2127,#2128,#2129));
#2131=FACE_BOUND('',#2130,.T.);
#2132=ADVANCED_FACE('F705',(#2131),#2120,.T.);
#2133=CARTESIAN_POINT('',(12.6111,-19.1389,12.7));
#2134=DIRECTION('',(0.,0.,-1.));
#2135=DIRECTION('',(-1.,0.,0.));
#2136=AXIS2_PLACEMENT_3D('',#2133,#2134,#2135);
#2137=CYLINDRICAL_SURFACE('',#2136,1.4986);
#2138=ORIENTED_EDGE('',*,*,#1703,.F.);
#2139=DIRECTION('',(0.,0.,-1.));
#2140=VECTOR('',#2139,1.);
#2141=CARTESIAN_POINT('',(12.6111,-20.6375,12.7));
#2142=LINE('',#2141,#2140);
#2143=EDGE_CURVE('E1746',#1139,#1693,#2142,.T.);
#2144=ORIENTED_EDGE('',*,*,#2143,.F.);
#2145=ORIENTED_EDGE('',*,*,#1140,.T.);
#2146=ORIENTED_EDGE('',*,*,#2126,.T.);
#2147=EDGE_LOOP('',(#2138,#2144,#2145,#2146));
#2148=FACE_BOUND('',#2147,.T.);
#2149=ADVANCED_FACE('F715',(#2148),#2137,.T.);
#2150=CARTESIAN_POINT('',(19.1389,-20.6375,12.7));
#2151=DIRECTION('',(0.,-1.,0.));
#2152=DIRECTION('',(1.,0.,0.));
#2153=AXIS2_PLACEMENT_3D('',#2150,#2151,#2152);
#2154=PLANE('',#2153);
#2155=ORIENTED_EDGE('',*,*,#1694,.F.);
#2156=DIRECTION('',(0.,0.,-1.));
#2157=VECTOR('',#2156,1.);
#2158=CARTESIAN_POINT('',(19.1389,-20.6375,12.7));
#2159=LINE('',#2158,#2157);
#2160=EDGE_CURVE('E1743',#1147,#1685,#2159,.T.);
#2161=ORIENTED_EDGE('',*,*,#2160,.F.);
#2162=ORIENTED_EDGE('',*,*,#1148,.T.);
#2163=ORIENTED_EDGE('',*,*,#2143,.T.);
#2164=EDGE_LOOP('',(#2155,#2161,#2162,#2163));
#2165=FACE_BOUND('',#2164,.T.);
#2166=ADVANCED_FACE('F725',(#2165),#2154,.T.);
#2167=CARTESIAN_POINT('',(19.1389,-19.1389,12.7));
#2168=DIRECTION('',(0.,0.,-1.));
#2169=DIRECTION('',(-1.,0.,0.));
#2170=AXIS2_PLACEMENT_3D('',#2167,#2168,#2169);
#2171=CYLINDRICAL_SURFACE('',#2170,1.4986);
#2172=ORIENTED_EDGE('',*,*,#1686,.F.);
#2173=DIRECTION('',(0.,0.,-1.));
#2174=VECTOR('',#2173,1.);
#2175=CARTESIAN_POINT('',(20.6375,-19.1389,12.7));
#2176=LINE('',#2175,#2174);
#2177=EDGE_CURVE('E1740',#1156,#1676,#2176,.T.);
#2178=ORIENTED_EDGE('',*,*,#2177,.F.);
#2179=ORIENTED_EDGE('',*,*,#1157,.T.);
#2180=ORIENTED_EDGE('',*,*,#2160,.T.);
#2181=EDGE_LOOP('',(#2172,#2178,#2179,#2180));
#2182=FACE_BOUND('',#2181,.T.);
#2183=ADVANCED_FACE('F735',(#2182),#2171,.T.);
#2184=CARTESIAN_POINT('',(22.1361,-8.69949999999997,12.7));
#2185=DIRECTION('',(0.,0.,-1.));
#2186=DIRECTION('',(-1.,0.,0.));
#2187=AXIS2_PLACEMENT_3D('',#2184,#2185,#2186);
#2188=CYLINDRICAL_SURFACE('',#2187,2.9972);
#2189=ORIENTED_EDGE('',*,*,#1934,.F.);
#2190=DIRECTION('',(0.,0.,-1.));
#2191=VECTOR('',#2190,1.);
#2192=CARTESIAN_POINT('',(20.6375,-6.10384865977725,12.7));
#2193=LINE('',#2192,#2191);
#2194=EDGE_CURVE('E1734',#1407,#1931,#2193,.T.);
#2195=ORIENTED_EDGE('',*,*,#2194,.F.);
#2196=ORIENTED_EDGE('',*,*,#1417,.T.);
#2197=DIRECTION('',(0.,0.,-1.));
#2198=VECTOR('',#2197,1.);
#2199=CARTESIAN_POINT('',(20.6375,-11.2951513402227,12.7));
#2200=LINE('',#2199,#2198);
#2201=EDGE_CURVE('E1737',#1409,#1933,#2200,.T.);
#2202=ORIENTED_EDGE('',*,*,#2201,.T.);
#2203=EDGE_LOOP('',(#2189,#2195,#2196,#2202));
#2204=FACE_BOUND('',#2203,.T.);
#2205=ADVANCED_FACE('F746',(#2204),#2188,.F.);
#2206=CARTESIAN_POINT('',(19.1389,-1.49860000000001,12.7));
#2207=DIRECTION('',(0.,0.,-1.));
#2208=DIRECTION('',(-1.,0.,0.));
#2209=AXIS2_PLACEMENT_3D('',#2206,#2207,#2208);
#2210=CYLINDRICAL_SURFACE('',#2209,1.4986);
#2211=ORIENTED_EDGE('',*,*,#1921,.F.);
#2212=ORIENTED_EDGE('',*,*,#445,.F.);
#2213=ORIENTED_EDGE('',*,*,#1402,.T.);
#2214=DIRECTION('',(0.,0.,-1.));
#2215=VECTOR('',#2214,1.);
#2216=CARTESIAN_POINT('',(20.6375,-1.49860000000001,12.7));
#2217=LINE('',#2216,#2215);
#2218=EDGE_CURVE('E1731',#1394,#1912,#2217,.T.);
#2219=ORIENTED_EDGE('',*,*,#2218,.T.);
#2220=EDGE_LOOP('',(#2211,#2212,#2213,#2219));
#2221=FACE_BOUND('',#2220,.T.);
#2222=ADVANCED_FACE('F756',(#2221),#2210,.T.);
#2223=CARTESIAN_POINT('',(-19.1389,-1.4986,12.7));
#2224=DIRECTION('',(0.,0.,-1.));
#2225=DIRECTION('',(-1.,0.,0.));
#2226=AXIS2_PLACEMENT_3D('',#2223,#2224,#2225);
#2227=CYLINDRICAL_SURFACE('',#2226,1.4986);
#2228=ORIENTED_EDGE('',*,*,#1883,.F.);
#2229=DIRECTION('',(0.,0.,-1.));
#2230=VECTOR('',#2229,1.);
#2231=CARTESIAN_POINT('',(-20.6375,-1.4986,12.7));
#2232=LINE('',#2231,#2230);
#2233=EDGE_CURVE('E1728',#957,#1875,#2232,.T.);
#2234=ORIENTED_EDGE('',*,*,#2233,.F.);
#2235=ORIENTED_EDGE('',*,*,#958,.T.);
#2236=ORIENTED_EDGE('',*,*,#395,.T.);
#2237=EDGE_LOOP('',(#2228,#2234,#2235,#2236));
#2238=FACE_BOUND('',#2237,.T.);
#2239=ADVANCED_FACE('F766',(#2238),#2227,.T.);
#2240=CARTESIAN_POINT('',(-20.6375,-6.10384865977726,12.7));
#2241=DIRECTION('',(-1.,0.,0.));
#2242=DIRECTION('',(0.,0.,1.));
#2243=AXIS2_PLACEMENT_3D('',#2240,#2241,#2242);
#2244=PLANE('',#2243);
#2245=ORIENTED_EDGE('',*,*,#1876,.F.);
#2246=DIRECTION('',(0.,0.,-1.));
#2247=VECTOR('',#2246,1.);
#2248=CARTESIAN_POINT('',(-20.6375,-6.10384865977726,12.7));
#2249=LINE('',#2248,#2247);
#2250=EDGE_CURVE('E1725',#965,#1867,#2249,.T.);
#2251=ORIENTED_EDGE('',*,*,#2250,.F.);
#2252=ORIENTED_EDGE('',*,*,#966,.T.);
#2253=ORIENTED_EDGE('',*,*,#2233,.T.);
#2254=EDGE_LOOP('',(#2245,#2251,#2252,#2253));
#2255=FACE_BOUND('',#2254,.T.);
#2256=ADVANCED_FACE('F776',(#2255),#2244,.T.);
#2257=CARTESIAN_POINT('',(-22.1361,-8.69949999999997,12.7));
#2258=DIRECTION('',(0.,0.,-1.));
#2259=DIRECTION('',(-1.,0.,0.));
#2260=AXIS2_PLACEMENT_3D('',#2257,#2258,#2259);
#2261=CYLINDRICAL_SURFACE('',#2260,2.9972);
#2262=ORIENTED_EDGE('',*,*,#1868,.F.);
#2263=DIRECTION('',(0.,0.,-1.));
#2264=VECTOR('',#2263,1.);
#2265=CARTESIAN_POINT('',(-20.6375,-11.2951513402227,12.7));
#2266=LINE('',#2265,#2264);
#2267=EDGE_CURVE('E1722',#974,#1858,#2266,.T.);
#2268=ORIENTED_EDGE('',*,*,#2267,.F.);
#2269=ORIENTED_EDGE('',*,*,#975,.T.);
#2270=ORIENTED_EDGE('',*,*,#2250,.T.);
#2271=EDGE_LOOP('',(#2262,#2268,#2269,#2270));
#2272=FACE_BOUND('',#2271,.T.);
#2273=ADVANCED_FACE('F786',(#2272),#2261,.F.);
#2274=CARTESIAN_POINT('',(-20.6375,-19.1389,12.7));
#2275=DIRECTION('',(-1.,0.,0.));
#2276=DIRECTION('',(0.,-1.,0.));
#2277=AXIS2_PLACEMENT_3D('',#2274,#2275,#2276);
#2278=PLANE('',#2277);
#2279=ORIENTED_EDGE('',*,*,#1859,.F.);
#2280=DIRECTION('',(0.,0.,-1.));
#2281=VECTOR('',#2280,1.);
#2282=CARTESIAN_POINT('',(-20.6375,-19.1389,12.7));
#2283=LINE('',#2282,#2281);
#2284=EDGE_CURVE('E1719',#982,#1850,#2283,.T.);
#2285=ORIENTED_EDGE('',*,*,#2284,.F.);
#2286=ORIENTED_EDGE('',*,*,#983,.T.);
#2287=ORIENTED_EDGE('',*,*,#2267,.T.);
#2288=EDGE_LOOP('',(#2279,#2285,#2286,#2287));
#2289=FACE_BOUND('',#2288,.T.);
#2290=ADVANCED_FACE('F796',(#2289),#2278,.T.);
#2291=CARTESIAN_POINT('',(-19.1389,-19.1389,12.7));
#2292=DIRECTION('',(0.,0.,-1.));
#2293=DIRECTION('',(-1.,0.,0.));
#2294=AXIS2_PLACEMENT_3D('',#2291,#2292,#2293);
#2295=CYLINDRICAL_SURFACE('',#2294,1.4986);
#2296=ORIENTED_EDGE('',*,*,#1851,.F.);
#2297=DIRECTION('',(0.,0.,-1.));
#2298=VECTOR('',#2297,1.);
#2299=CARTESIAN_POINT('',(-19.1389,-20.6375,12.7));
#2300=LINE('',#2299,#2298);
#2301=EDGE_CURVE('E1716',#991,#1841,#2300,.T.);
#2302=ORIENTED_EDGE('',*,*,#2301,.F.);
#2303=ORIENTED_EDGE('',*,*,#992,.T.);
#2304=ORIENTED_EDGE('',*,*,#2284,.T.);
#2305=EDGE_LOOP('',(#2296,#2302,#2303,#2304));
#2306=FACE_BOUND('',#2305,.T.);
#2307=ADVANCED_FACE('F806',(#2306),#2295,.T.);
#2308=CARTESIAN_POINT('',(-19.1389,-20.6375,12.7));
#2309=DIRECTION('',(0.,-1.,0.));
#2310=DIRECTION('',(0.,0.,-1.));
#2311=AXIS2_PLACEMENT_3D('',#2308,#2309,#2310);
#2312=PLANE('',#2311);
#2313=ORIENTED_EDGE('',*,*,#1842,.F.);
#2314=DIRECTION('',(0.,0.,-1.));
#2315=VECTOR('',#2314,1.);
#2316=CARTESIAN_POINT('',(-12.6111,-20.6375,12.7));
#2317=LINE('',#2316,#2315);
#2318=EDGE_CURVE('E1713',#999,#1833,#2317,.T.);
#2319=ORIENTED_EDGE('',*,*,#2318,.F.);
#2320=ORIENTED_EDGE('',*,*,#1000,.T.);
#2321=ORIENTED_EDGE('',*,*,#2301,.T.);
#2322=EDGE_LOOP('',(#2313,#2319,#2320,#2321));
#2323=FACE_BOUND('',#2322,.T.);
#2324=ADVANCED_FACE('F816',(#2323),#2312,.T.);
#2325=CARTESIAN_POINT('',(-12.6111,-19.1389,12.7));
#2326=DIRECTION('',(0.,0.,-1.));
#2327=DIRECTION('',(-1.,0.,0.));
#2328=AXIS2_PLACEMENT_3D('',#2325,#2326,#2327);
#2329=CYLINDRICAL_SURFACE('',#2328,1.4986);
#2330=ORIENTED_EDGE('',*,*,#1834,.F.);
#2331=DIRECTION('',(0.,0.,-1.));
#2332=VECTOR('',#2331,1.);
#2333=CARTESIAN_POINT('',(-11.1125,-19.1389,12.7));
#2334=LINE('',#2333,#2332);
#2335=EDGE_CURVE('E1710',#1008,#1824,#2334,.T.);
#2336=ORIENTED_EDGE('',*,*,#2335,.F.);
#2337=ORIENTED_EDGE('',*,*,#1009,.T.);
#2338=ORIENTED_EDGE('',*,*,#2318,.T.);
#2339=EDGE_LOOP('',(#2330,#2336,#2337,#2338));
#2340=FACE_BOUND('',#2339,.T.);
#2341=ADVANCED_FACE('F826',(#2340),#2329,.T.);
#2342=CARTESIAN_POINT('',(-11.1125,-19.1389,12.7));
#2343=DIRECTION('',(1.,0.,0.));
#2344=DIRECTION('',(0.,1.,0.));
#2345=AXIS2_PLACEMENT_3D('',#2342,#2343,#2344);
#2346=PLANE('',#2345);
#2347=ORIENTED_EDGE('',*,*,#1825,.F.);
#2348=DIRECTION('',(0.,0.,-1.));
#2349=VECTOR('',#2348,1.);
#2350=CARTESIAN_POINT('',(-11.1125,-14.2875,12.7));
#2351=LINE('',#2350,#2349);
#2352=EDGE_CURVE('E1707',#1016,#1816,#2351,.T.);
#2353=ORIENTED_EDGE('',*,*,#2352,.F.);
#2354=ORIENTED_EDGE('',*,*,#1017,.T.);
#2355=ORIENTED_EDGE('',*,*,#2335,.T.);
#2356=EDGE_LOOP('',(#2347,#2353,#2354,#2355));
#2357=FACE_BOUND('',#2356,.T.);
#2358=ADVANCED_FACE('F836',(#2357),#2346,.T.);
#2359=CARTESIAN_POINT('',(-12.6111,-14.2875,12.7));
#2360=DIRECTION('',(0.,1.,0.));
#2361=DIRECTION('',(0.,0.,1.));
#2362=AXIS2_PLACEMENT_3D('',#2359,#2360,#2361);
#2363=PLANE('',#2362);
#2364=ORIENTED_EDGE('',*,*,#1817,.F.);
#2365=DIRECTION('',(0.,0.,-1.));
#2366=VECTOR('',#2365,1.);
#2367=CARTESIAN_POINT('',(-12.6111,-14.2875,12.7));
#2368=LINE('',#2367,#2366);
#2369=EDGE_CURVE('E1704',#1024,#1808,#2368,.T.);
#2370=ORIENTED_EDGE('',*,*,#2369,.F.);
#2371=ORIENTED_EDGE('',*,*,#1025,.T.);
#2372=ORIENTED_EDGE('',*,*,#2352,.T.);
#2373=EDGE_LOOP('',(#2364,#2370,#2371,#2372));
#2374=FACE_BOUND('',#2373,.T.);
#2375=ADVANCED_FACE('F846',(#2374),#2363,.T.);
#2376=CARTESIAN_POINT('',(-12.6111,-19.1389,12.7));
#2377=DIRECTION('',(-1.,0.,0.));
#2378=DIRECTION('',(0.,-1.,0.));
#2379=AXIS2_PLACEMENT_3D('',#2376,#2377,#2378);
#2380=PLANE('',#2379);
#2381=ORIENTED_EDGE('',*,*,#1809,.F.);
#2382=DIRECTION('',(0.,0.,-1.));
#2383=VECTOR('',#2382,1.);
#2384=CARTESIAN_POINT('',(-12.6111,-19.1389,12.7));
#2385=LINE('',#2384,#2383);
#2386=EDGE_CURVE('E1701',#1032,#1800,#2385,.T.);
#2387=ORIENTED_EDGE('',*,*,#2386,.F.);
#2388=ORIENTED_EDGE('',*,*,#1033,.T.);
#2389=ORIENTED_EDGE('',*,*,#2369,.T.);
#2390=EDGE_LOOP('',(#2381,#2387,#2388,#2389));
#2391=FACE_BOUND('',#2390,.T.);
#2392=ADVANCED_FACE('F856',(#2391),#2380,.T.);
#2393=CARTESIAN_POINT('',(-19.1389,-19.1389,12.7));
#2394=DIRECTION('',(0.,1.,0.));
#2395=DIRECTION('',(0.,0.,1.));
#2396=AXIS2_PLACEMENT_3D('',#2393,#2394,#2395);
#2397=PLANE('',#2396);
#2398=ORIENTED_EDGE('',*,*,#1801,.F.);
#2399=ORIENTED_EDGE('',*,*,#1958,.F.);
#2400=ORIENTED_EDGE('',*,*,#1041,.T.);
#2401=ORIENTED_EDGE('',*,*,#2386,.T.);
#2402=EDGE_LOOP('',(#2398,#2399,#2400,#2401));
#2403=FACE_BOUND('',#2402,.T.);
#2404=ADVANCED_FACE('F866',(#2403),#2397,.T.);
#2405=CARTESIAN_POINT('',(20.6375,19.1389,12.7));
#2406=DIRECTION('',(1.,0.,0.));
#2407=DIRECTION('',(0.,0.,-1.));
#2408=AXIS2_PLACEMENT_3D('',#2405,#2406,#2407);
#2409=PLANE('',#2408);
#2410=ORIENTED_EDGE('',*,*,#1395,.F.);
#2411=ORIENTED_EDGE('',*,*,#430,.T.);
#2412=ORIENTED_EDGE('',*,*,#1913,.T.);
#2413=ORIENTED_EDGE('',*,*,#2218,.F.);
#2414=EDGE_LOOP('',(#2410,#2411,#2412,#2413));
#2415=FACE_BOUND('',#2414,.T.);
#2416=ADVANCED_FACE('F875',(#2415),#2409,.F.);
#2417=ORIENTED_EDGE('',*,*,#1432,.T.);
#2418=ORIENTED_EDGE('',*,*,#487,.F.);
#2419=ORIENTED_EDGE('',*,*,#912,.F.);
#2420=ORIENTED_EDGE('',*,*,#472,.T.);
#2421=EDGE_LOOP('',(#2417,#2418,#2419,#2420));
#2422=FACE_BOUND('',#2421,.T.);
#2423=ADVANCED_FACE('F1026',(#2422),#2409,.F.);
#2424=CARTESIAN_POINT('',(39.7764,19.1389,12.7));
#2425=DIRECTION('',(0.,1.,0.));
#2426=DIRECTION('',(0.,0.,1.));
#2427=AXIS2_PLACEMENT_3D('',#2424,#2425,#2426);
#2428=PLANE('',#2427);
#2429=ORIENTED_EDGE('',*,*,#1535,.T.);
#2430=DIRECTION('',(0.,0.,-1.));
#2431=VECTOR('',#2430,1.);
#2432=CARTESIAN_POINT('',(39.7764,19.1389,12.7));
#2433=LINE('',#2432,#2431);
#2434=EDGE_CURVE('E1534',#1306,#1526,#2433,.T.);
#2435=ORIENTED_EDGE('',*,*,#2434,.F.);
#2436=ORIENTED_EDGE('',*,*,#1307,.F.);
#2437=DIRECTION('',(0.,0.,-1.));
#2438=VECTOR('',#2437,1.);
#2439=CARTESIAN_POINT('',(32.6879714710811,19.1389,12.7));
#2440=LINE('',#2439,#2438);
#2441=EDGE_CURVE('E1347',#1298,#1534,#2440,.T.);
#2442=ORIENTED_EDGE('',*,*,#2441,.T.);
#2443=EDGE_LOOP('',(#2429,#2435,#2436,#2442));
#2444=FACE_BOUND('',#2443,.T.);
#2445=ADVANCED_FACE('F1036',(#2444),#2428,.F.);
#2446=CARTESIAN_POINT('',(39.7764,19.1389,12.7));
#2447=DIRECTION('',(1.,0.,0.));
#2448=DIRECTION('',(0.,0.,-1.));
#2449=AXIS2_PLACEMENT_3D('',#2446,#2447,#2448);
#2450=PLANE('',#2449);
#2451=ORIENTED_EDGE('',*,*,#1527,.T.);
#2452=DIRECTION('',(0.,0.,-1.));
#2453=VECTOR('',#2452,1.);
#2454=CARTESIAN_POINT('',(39.7764,12.6111,12.7));
#2455=LINE('',#2454,#2453);
#2456=EDGE_CURVE('E1531',#1314,#1518,#2455,.T.);
#2457=ORIENTED_EDGE('',*,*,#2456,.F.);
#2458=ORIENTED_EDGE('',*,*,#1315,.F.);
#2459=ORIENTED_EDGE('',*,*,#2434,.T.);
#2460=EDGE_LOOP('',(#2451,#2457,#2458,#2459));
#2461=FACE_BOUND('',#2460,.T.);
#2462=ADVANCED_FACE('F1044',(#2461),#2450,.F.);
#2463=CARTESIAN_POINT('',(39.7764,12.6111,12.7));
#2464=DIRECTION('',(0.,-1.,0.));
#2465=DIRECTION('',(1.,0.,0.));
#2466=AXIS2_PLACEMENT_3D('',#2463,#2464,#2465);
#2467=PLANE('',#2466);
#2468=ORIENTED_EDGE('',*,*,#1519,.T.);
#2469=DIRECTION('',(0.,0.,-1.));
#2470=VECTOR('',#2469,1.);
#2471=CARTESIAN_POINT('',(34.925,12.6111,12.7));
#2472=LINE('',#2471,#2470);
#2473=EDGE_CURVE('E1528',#1322,#1510,#2472,.T.);
#2474=ORIENTED_EDGE('',*,*,#2473,.F.);
#2475=ORIENTED_EDGE('',*,*,#1323,.F.);
#2476=ORIENTED_EDGE('',*,*,#2456,.T.);
#2477=EDGE_LOOP('',(#2468,#2474,#2475,#2476));
#2478=FACE_BOUND('',#2477,.T.);
#2479=ADVANCED_FACE('F1053',(#2478),#2467,.F.);
#2480=CARTESIAN_POINT('',(34.925,12.6111,12.7));
#2481=DIRECTION('',(1.,0.,0.));
#2482=DIRECTION('',(0.,0.,-1.));
#2483=AXIS2_PLACEMENT_3D('',#2480,#2481,#2482);
#2484=PLANE('',#2483);
#2485=ORIENTED_EDGE('',*,*,#1511,.T.);
#2486=DIRECTION('',(0.,0.,-1.));
#2487=VECTOR('',#2486,1.);
#2488=CARTESIAN_POINT('',(34.925,11.1125,12.7));
#2489=LINE('',#2488,#2487);
#2490=EDGE_CURVE('E1525',#1330,#1502,#2489,.T.);
#2491=ORIENTED_EDGE('',*,*,#2490,.F.);
#2492=ORIENTED_EDGE('',*,*,#1331,.F.);
#2493=ORIENTED_EDGE('',*,*,#2473,.T.);
#2494=EDGE_LOOP('',(#2485,#2491,#2492,#2493));
#2495=FACE_BOUND('',#2494,.T.);
#2496=ADVANCED_FACE('F1062',(#2495),#2484,.F.);
#2497=CARTESIAN_POINT('',(39.7764,11.1125,12.7));
#2498=DIRECTION('',(0.,1.,0.));
#2499=DIRECTION('',(0.,0.,1.));
#2500=AXIS2_PLACEMENT_3D('',#2497,#2498,#2499);
#2501=PLANE('',#2500);
#2502=ORIENTED_EDGE('',*,*,#1503,.T.);
#2503=DIRECTION('',(0.,0.,-1.));
#2504=VECTOR('',#2503,1.);
#2505=CARTESIAN_POINT('',(39.7764,11.1125,12.7));
#2506=LINE('',#2505,#2504);
#2507=EDGE_CURVE('E1522',#1338,#1494,#2506,.T.);
#2508=ORIENTED_EDGE('',*,*,#2507,.F.);
#2509=ORIENTED_EDGE('',*,*,#1339,.F.);
#2510=ORIENTED_EDGE('',*,*,#2490,.T.);
#2511=EDGE_LOOP('',(#2502,#2508,#2509,#2510));
#2512=FACE_BOUND('',#2511,.T.);
#2513=ADVANCED_FACE('F1071',(#2512),#2501,.F.);
#2514=CARTESIAN_POINT('',(39.7764,12.6111,12.7));
#2515=DIRECTION('',(0.,0.,-1.));
#2516=DIRECTION('',(-1.,0.,0.));
#2517=AXIS2_PLACEMENT_3D('',#2514,#2515,#2516);
#2518=CYLINDRICAL_SURFACE('',#2517,1.4986);
#2519=ORIENTED_EDGE('',*,*,#1495,.T.);
#2520=DIRECTION('',(0.,0.,-1.));
#2521=VECTOR('',#2520,1.);
#2522=CARTESIAN_POINT('',(41.275,12.6111,12.7));
#2523=LINE('',#2522,#2521);
#2524=EDGE_CURVE('E1519',#1347,#1485,#2523,.T.);
#2525=ORIENTED_EDGE('',*,*,#2524,.F.);
#2526=ORIENTED_EDGE('',*,*,#1348,.F.);
#2527=ORIENTED_EDGE('',*,*,#2507,.T.);
#2528=EDGE_LOOP('',(#2519,#2525,#2526,#2527));
#2529=FACE_BOUND('',#2528,.T.);
#2530=ADVANCED_FACE('F1080',(#2529),#2518,.T.);
#2531=CARTESIAN_POINT('',(41.275,19.1389,12.7));
#2532=DIRECTION('',(-1.,0.,0.));
#2533=DIRECTION('',(0.,0.,1.));
#2534=AXIS2_PLACEMENT_3D('',#2531,#2532,#2533);
#2535=PLANE('',#2534);
#2536=ORIENTED_EDGE('',*,*,#1486,.T.);
#2537=DIRECTION('',(0.,0.,-1.));
#2538=VECTOR('',#2537,1.);
#2539=CARTESIAN_POINT('',(41.275,19.1389,12.7));
#2540=LINE('',#2539,#2538);
#2541=EDGE_CURVE('E1516',#1355,#1477,#2540,.T.);
#2542=ORIENTED_EDGE('',*,*,#2541,.F.);
#2543=ORIENTED_EDGE('',*,*,#1356,.F.);
#2544=ORIENTED_EDGE('',*,*,#2524,.T.);
#2545=EDGE_LOOP('',(#2536,#2542,#2543,#2544));
#2546=FACE_BOUND('',#2545,.T.);
#2547=ADVANCED_FACE('F1089',(#2546),#2535,.F.);
#2548=CARTESIAN_POINT('',(39.7764,19.1389,12.7));
#2549=DIRECTION('',(0.,0.,-1.));
#2550=DIRECTION('',(-1.,0.,0.));
#2551=AXIS2_PLACEMENT_3D('',#2548,#2549,#2550);
#2552=CYLINDRICAL_SURFACE('',#2551,1.4986);
#2553=ORIENTED_EDGE('',*,*,#1478,.T.);
#2554=DIRECTION('',(0.,0.,-1.));
#2555=VECTOR('',#2554,1.);
#2556=CARTESIAN_POINT('',(39.7764,20.6375,12.7));
#2557=LINE('',#2556,#2555);
#2558=EDGE_CURVE('E1513',#1364,#1468,#2557,.T.);
#2559=ORIENTED_EDGE('',*,*,#2558,.F.);
#2560=ORIENTED_EDGE('',*,*,#1365,.F.);
#2561=ORIENTED_EDGE('',*,*,#2541,.T.);
#2562=EDGE_LOOP('',(#2553,#2559,#2560,#2561));
#2563=FACE_BOUND('',#2562,.T.);
#2564=ADVANCED_FACE('F1098',(#2563),#2552,.T.);
#2565=CARTESIAN_POINT('',(39.7764,20.6375,12.7));
#2566=DIRECTION('',(0.,-1.,0.));
#2567=DIRECTION('',(0.,0.,-1.));
#2568=AXIS2_PLACEMENT_3D('',#2565,#2566,#2567);
#2569=PLANE('',#2568);
#2570=ORIENTED_EDGE('',*,*,#1469,.T.);
#2571=DIRECTION('',(0.,0.,-1.));
#2572=VECTOR('',#2571,1.);
#2573=CARTESIAN_POINT('',(31.9326513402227,20.6375,12.7));
#2574=LINE('',#2573,#2572);
#2575=EDGE_CURVE('E1510',#1372,#1460,#2574,.T.);
#2576=ORIENTED_EDGE('',*,*,#2575,.F.);
#2577=ORIENTED_EDGE('',*,*,#1373,.F.);
#2578=ORIENTED_EDGE('',*,*,#2558,.T.);
#2579=EDGE_LOOP('',(#2570,#2576,#2577,#2578));
#2580=FACE_BOUND('',#2579,.T.);
#2581=ADVANCED_FACE('F1107',(#2580),#2569,.F.);
#2582=CARTESIAN_POINT('',(29.337,22.1361,12.7));
#2583=DIRECTION('',(0.,0.,-1.));
#2584=DIRECTION('',(-1.,0.,0.));
#2585=AXIS2_PLACEMENT_3D('',#2582,#2583,#2584);
#2586=CYLINDRICAL_SURFACE('',#2585,2.9972);
#2587=ORIENTED_EDGE('',*,*,#1461,.T.);
#2588=DIRECTION('',(0.,0.,-1.));
#2589=VECTOR('',#2588,1.);
#2590=CARTESIAN_POINT('',(26.7413486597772,20.6375,12.7));
#2591=LINE('',#2590,#2589);
#2592=EDGE_CURVE('E1507',#1381,#1451,#2591,.T.);
#2593=ORIENTED_EDGE('',*,*,#2592,.F.);
#2594=ORIENTED_EDGE('',*,*,#1382,.F.);
#2595=ORIENTED_EDGE('',*,*,#2575,.T.);
#2596=EDGE_LOOP('',(#2587,#2593,#2594,#2595));
#2597=FACE_BOUND('',#2596,.T.);
#2598=ADVANCED_FACE('F1116',(#2597),#2586,.F.);
#2599=CARTESIAN_POINT('',(26.7413486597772,20.6375,12.7));
#2600=DIRECTION('',(0.,-1.,0.));
#2601=DIRECTION('',(1.,0.,0.));
#2602=AXIS2_PLACEMENT_3D('',#2599,#2600,#2601);
#2603=PLANE('',#2602);
#2604=ORIENTED_EDGE('',*,*,#1452,.T.);
#2605=DIRECTION('',(0.,0.,-1.));
#2606=VECTOR('',#2605,1.);
#2607=CARTESIAN_POINT('',(22.1361,20.6375,12.7));
#2608=LINE('',#2607,#2606);
#2609=EDGE_CURVE('E1504',#923,#1443,#2608,.T.);
#2610=ORIENTED_EDGE('',*,*,#2609,.F.);
#2611=ORIENTED_EDGE('',*,*,#1388,.F.);
#2612=ORIENTED_EDGE('',*,*,#2592,.T.);
#2613=EDGE_LOOP('',(#2604,#2610,#2611,#2612));
#2614=FACE_BOUND('',#2613,.T.);
#2615=ADVANCED_FACE('F1125',(#2614),#2603,.F.);
#2616=CARTESIAN_POINT('',(22.1361,19.1389,12.7));
#2617=DIRECTION('',(0.,0.,-1.));
#2618=DIRECTION('',(-1.,0.,0.));
#2619=AXIS2_PLACEMENT_3D('',#2616,#2617,#2618);
#2620=CYLINDRICAL_SURFACE('',#2619,1.4986);
#2621=ORIENTED_EDGE('',*,*,#1444,.T.);
#2622=ORIENTED_EDGE('',*,*,#529,.F.);
#2623=ORIENTED_EDGE('',*,*,#924,.F.);
#2624=ORIENTED_EDGE('',*,*,#2609,.T.);
#2625=EDGE_LOOP('',(#2621,#2622,#2623,#2624));
#2626=FACE_BOUND('',#2625,.T.);
#2627=ADVANCED_FACE('F1134',(#2626),#2620,.T.);
#2628=ORIENTED_EDGE('',*,*,#2201,.F.);
#2629=ORIENTED_EDGE('',*,*,#1410,.F.);
#2630=ORIENTED_EDGE('',*,*,#2194,.T.);
#2631=ORIENTED_EDGE('',*,*,#1936,.T.);
#2632=EDGE_LOOP('',(#2628,#2629,#2630,#2631));
#2633=FACE_BOUND('',#2632,.T.);
#2634=ADVANCED_FACE('F1029',(#2633),#2409,.F.);
#2635=CARTESIAN_POINT('',(22.1361,-19.1389,12.7));
#2636=DIRECTION('',(0.,0.,-1.));
#2637=DIRECTION('',(-1.,0.,0.));
#2638=AXIS2_PLACEMENT_3D('',#2635,#2636,#2637);
#2639=CYLINDRICAL_SURFACE('',#2638,1.4986);
#2640=ORIENTED_EDGE('',*,*,#1677,.T.);
#2641=DIRECTION('',(0.,0.,-1.));
#2642=VECTOR('',#2641,1.);
#2643=CARTESIAN_POINT('',(22.1361,-20.6375,12.7));
#2644=LINE('',#2643,#2642);
#2645=EDGE_CURVE('E1501',#1165,#1667,#2644,.T.);
#2646=ORIENTED_EDGE('',*,*,#2645,.F.);
#2647=ORIENTED_EDGE('',*,*,#1166,.F.);
#2648=ORIENTED_EDGE('',*,*,#2177,.T.);
#2649=EDGE_LOOP('',(#2640,#2646,#2647,#2648));
#2650=FACE_BOUND('',#2649,.T.);
#2651=ADVANCED_FACE('F1151',(#2650),#2639,.T.);
#2652=CARTESIAN_POINT('',(22.1361,-20.6375,12.7));
#2653=DIRECTION('',(0.,1.,0.));
#2654=DIRECTION('',(-1.,0.,0.));
#2655=AXIS2_PLACEMENT_3D('',#2652,#2653,#2654);
#2656=PLANE('',#2655);
#2657=ORIENTED_EDGE('',*,*,#1668,.T.);
#2658=DIRECTION('',(0.,0.,-1.));
#2659=VECTOR('',#2658,1.);
#2660=CARTESIAN_POINT('',(26.7413486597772,-20.6375,12.7));
#2661=LINE('',#2660,#2659);
#2662=EDGE_CURVE('E1498',#1173,#1659,#2661,.T.);
#2663=ORIENTED_EDGE('',*,*,#2662,.F.);
#2664=ORIENTED_EDGE('',*,*,#1174,.F.);
#2665=ORIENTED_EDGE('',*,*,#2645,.T.);
#2666=EDGE_LOOP('',(#2657,#2663,#2664,#2665));
#2667=FACE_BOUND('',#2666,.T.);
#2668=ADVANCED_FACE('F1159',(#2667),#2656,.F.);
#2669=CARTESIAN_POINT('',(29.337,-22.1361,12.7));
#2670=DIRECTION('',(0.,0.,-1.));
#2671=DIRECTION('',(-1.,0.,0.));
#2672=AXIS2_PLACEMENT_3D('',#2669,#2670,#2671);
#2673=CYLINDRICAL_SURFACE('',#2672,2.9972);
#2674=ORIENTED_EDGE('',*,*,#1660,.T.);
#2675=DIRECTION('',(0.,0.,-1.));
#2676=VECTOR('',#2675,1.);
#2677=CARTESIAN_POINT('',(31.9326513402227,-20.6375,12.7));
#2678=LINE('',#2677,#2676);
#2679=EDGE_CURVE('E1495',#1182,#1650,#2678,.T.);
#2680=ORIENTED_EDGE('',*,*,#2679,.F.);
#2681=ORIENTED_EDGE('',*,*,#1183,.F.);
#2682=ORIENTED_EDGE('',*,*,#2662,.T.);
#2683=EDGE_LOOP('',(#2674,#2680,#2681,#2682));
#2684=FACE_BOUND('',#2683,.T.);
#2685=ADVANCED_FACE('F1168',(#2684),#2673,.F.);
#2686=CARTESIAN_POINT('',(31.9326513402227,-20.6375,12.7));
#2687=DIRECTION('',(0.,1.,0.));
#2688=DIRECTION('',(-1.,0.,0.));
#2689=AXIS2_PLACEMENT_3D('',#2686,#2687,#2688);
#2690=PLANE('',#2689);
#2691=ORIENTED_EDGE('',*,*,#1651,.T.);
#2692=DIRECTION('',(0.,0.,-1.));
#2693=VECTOR('',#2692,1.);
#2694=CARTESIAN_POINT('',(39.7764,-20.6375,12.7));
#2695=LINE('',#2694,#2693);
#2696=EDGE_CURVE('E1492',#1190,#1642,#2695,.T.);
#2697=ORIENTED_EDGE('',*,*,#2696,.F.);
#2698=ORIENTED_EDGE('',*,*,#1191,.F.);
#2699=ORIENTED_EDGE('',*,*,#2679,.T.);
#2700=EDGE_LOOP('',(#2691,#2697,#2698,#2699));
#2701=FACE_BOUND('',#2700,.T.);
#2702=ADVANCED_FACE('F1177',(#2701),#2690,.F.);
#2703=CARTESIAN_POINT('',(39.7764,-19.1389,12.7));
#2704=DIRECTION('',(0.,0.,-1.));
#2705=DIRECTION('',(-1.,0.,0.));
#2706=AXIS2_PLACEMENT_3D('',#2703,#2704,#2705);
#2707=CYLINDRICAL_SURFACE('',#2706,1.4986);
#2708=ORIENTED_EDGE('',*,*,#1643,.T.);
#2709=DIRECTION('',(0.,0.,-1.));
#2710=VECTOR('',#2709,1.);
#2711=CARTESIAN_POINT('',(41.275,-19.1389,12.7));
#2712=LINE('',#2711,#2710);
#2713=EDGE_CURVE('E1489',#1199,#1633,#2712,.T.);
#2714=ORIENTED_EDGE('',*,*,#2713,.F.);
#2715=ORIENTED_EDGE('',*,*,#1200,.F.);
#2716=ORIENTED_EDGE('',*,*,#2696,.T.);
#2717=EDGE_LOOP('',(#2708,#2714,#2715,#2716));
#2718=FACE_BOUND('',#2717,.T.);
#2719=ADVANCED_FACE('F1186',(#2718),#2707,.T.);
#2720=CARTESIAN_POINT('',(41.275,-19.1389,12.7));
#2721=DIRECTION('',(-1.,0.,0.));
#2722=DIRECTION('',(0.,0.,1.));
#2723=AXIS2_PLACEMENT_3D('',#2720,#2721,#2722);
#2724=PLANE('',#2723);
#2725=ORIENTED_EDGE('',*,*,#1634,.T.);
#2726=DIRECTION('',(0.,0.,-1.));
#2727=VECTOR('',#2726,1.);
#2728=CARTESIAN_POINT('',(41.275,-12.6111,12.7));
#2729=LINE('',#2728,#2727);
#2730=EDGE_CURVE('E1486',#1207,#1625,#2729,.T.);
#2731=ORIENTED_EDGE('',*,*,#2730,.F.);
#2732=ORIENTED_EDGE('',*,*,#1208,.F.);
#2733=ORIENTED_EDGE('',*,*,#2713,.T.);
#2734=EDGE_LOOP('',(#2725,#2731,#2732,#2733));
#2735=FACE_BOUND('',#2734,.T.);
#2736=ADVANCED_FACE('F1195',(#2735),#2724,.F.);
#2737=CARTESIAN_POINT('',(39.7764,-12.6111,12.7));
#2738=DIRECTION('',(0.,0.,-1.));
#2739=DIRECTION('',(-1.,0.,0.));
#2740=AXIS2_PLACEMENT_3D('',#2737,#2738,#2739);
#2741=CYLINDRICAL_SURFACE('',#2740,1.49859999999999);
#2742=ORIENTED_EDGE('',*,*,#1626,.T.);
#2743=DIRECTION('',(0.,0.,-1.));
#2744=VECTOR('',#2743,1.);
#2745=CARTESIAN_POINT('',(39.7764,-11.1125,12.7));
#2746=LINE('',#2745,#2744);
#2747=EDGE_CURVE('E1483',#1216,#1616,#2746,.T.);
#2748=ORIENTED_EDGE('',*,*,#2747,.F.);
#2749=ORIENTED_EDGE('',*,*,#1217,.F.);
#2750=ORIENTED_EDGE('',*,*,#2730,.T.);
#2751=EDGE_LOOP('',(#2742,#2748,#2749,#2750));
#2752=FACE_BOUND('',#2751,.T.);
#2753=ADVANCED_FACE('F1204',(#2752),#2741,.T.);
#2754=CARTESIAN_POINT('',(39.7764,-11.1125,12.7));
#2755=DIRECTION('',(0.,-1.,0.));
#2756=DIRECTION('',(1.,0.,0.));
#2757=AXIS2_PLACEMENT_3D('',#2754,#2755,#2756);
#2758=PLANE('',#2757);
#2759=ORIENTED_EDGE('',*,*,#1617,.T.);
#2760=DIRECTION('',(0.,0.,-1.));
#2761=VECTOR('',#2760,1.);
#2762=CARTESIAN_POINT('',(34.925,-11.1125,12.7));
#2763=LINE('',#2762,#2761);
#2764=EDGE_CURVE('E1480',#1224,#1608,#2763,.T.);
#2765=ORIENTED_EDGE('',*,*,#2764,.F.);
#2766=ORIENTED_EDGE('',*,*,#1225,.F.);
#2767=ORIENTED_EDGE('',*,*,#2747,.T.);
#2768=EDGE_LOOP('',(#2759,#2765,#2766,#2767));
#2769=FACE_BOUND('',#2768,.T.);
#2770=ADVANCED_FACE('F1213',(#2769),#2758,.F.);
#2771=CARTESIAN_POINT('',(34.925,-11.1125,12.7));
#2772=DIRECTION('',(1.,0.,0.));
#2773=DIRECTION('',(0.,0.,-1.));
#2774=AXIS2_PLACEMENT_3D('',#2771,#2772,#2773);
#2775=PLANE('',#2774);
#2776=ORIENTED_EDGE('',*,*,#1609,.T.);
#2777=DIRECTION('',(0.,0.,-1.));
#2778=VECTOR('',#2777,1.);
#2779=CARTESIAN_POINT('',(34.925,-12.6111,12.7));
#2780=LINE('',#2779,#2778);
#2781=EDGE_CURVE('E1477',#1232,#1600,#2780,.T.);
#2782=ORIENTED_EDGE('',*,*,#2781,.F.);
#2783=ORIENTED_EDGE('',*,*,#1233,.F.);
#2784=ORIENTED_EDGE('',*,*,#2764,.T.);
#2785=EDGE_LOOP('',(#2776,#2782,#2783,#2784));
#2786=FACE_BOUND('',#2785,.T.);
#2787=ADVANCED_FACE('F1222',(#2786),#2775,.F.);
#2788=CARTESIAN_POINT('',(39.7764,-12.6111,12.7));
#2789=DIRECTION('',(0.,1.,0.));
#2790=DIRECTION('',(0.,0.,1.));
#2791=AXIS2_PLACEMENT_3D('',#2788,#2789,#2790);
#2792=PLANE('',#2791);
#2793=ORIENTED_EDGE('',*,*,#1601,.T.);
#2794=DIRECTION('',(0.,0.,-1.));
#2795=VECTOR('',#2794,1.);
#2796=CARTESIAN_POINT('',(39.7764,-12.6111,12.7));
#2797=LINE('',#2796,#2795);
#2798=EDGE_CURVE('E1474',#1240,#1592,#2797,.T.);
#2799=ORIENTED_EDGE('',*,*,#2798,.F.);
#2800=ORIENTED_EDGE('',*,*,#1241,.F.);
#2801=ORIENTED_EDGE('',*,*,#2781,.T.);
#2802=EDGE_LOOP('',(#2793,#2799,#2800,#2801));
#2803=FACE_BOUND('',#2802,.T.);
#2804=ADVANCED_FACE('F1231',(#2803),#2792,.F.);
#2805=CARTESIAN_POINT('',(39.7764,-19.1389,12.7));
#2806=DIRECTION('',(1.,0.,0.));
#2807=DIRECTION('',(0.,1.,0.));
#2808=AXIS2_PLACEMENT_3D('',#2805,#2806,#2807);
#2809=PLANE('',#2808);
#2810=ORIENTED_EDGE('',*,*,#1593,.T.);
#2811=DIRECTION('',(0.,0.,-1.));
#2812=VECTOR('',#2811,1.);
#2813=CARTESIAN_POINT('',(39.7764,-19.1389,12.7));
#2814=LINE('',#2813,#2812);
#2815=EDGE_CURVE('E1471',#1248,#1584,#2814,.T.);
#2816=ORIENTED_EDGE('',*,*,#2815,.F.);
#2817=ORIENTED_EDGE('',*,*,#1249,.F.);
#2818=ORIENTED_EDGE('',*,*,#2798,.T.);
#2819=EDGE_LOOP('',(#2810,#2816,#2817,#2818));
#2820=FACE_BOUND('',#2819,.T.);
#2821=ADVANCED_FACE('F1240',(#2820),#2809,.F.);
#2822=CARTESIAN_POINT('',(32.6879714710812,-19.1389,12.7));
#2823=DIRECTION('',(0.,-1.,0.));
#2824=DIRECTION('',(1.,0.,0.));
#2825=AXIS2_PLACEMENT_3D('',#2822,#2823,#2824);
#2826=PLANE('',#2825);
#2827=ORIENTED_EDGE('',*,*,#1585,.T.);
#2828=DIRECTION('',(0.,0.,-1.));
#2829=VECTOR('',#2828,1.);
#2830=CARTESIAN_POINT('',(32.6879714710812,-19.1389,12.7));
#2831=LINE('',#2830,#2829);
#2832=EDGE_CURVE('E1468',#1256,#1576,#2831,.T.);
#2833=ORIENTED_EDGE('',*,*,#2832,.F.);
#2834=ORIENTED_EDGE('',*,*,#1257,.F.);
#2835=ORIENTED_EDGE('',*,*,#2815,.T.);
#2836=EDGE_LOOP('',(#2827,#2833,#2834,#2835));
#2837=FACE_BOUND('',#2836,.T.);
#2838=ADVANCED_FACE('F1249',(#2837),#2826,.F.);
#2839=CARTESIAN_POINT('',(29.337,-22.1361,12.7));
#2840=DIRECTION('',(0.,0.,-1.));
#2841=DIRECTION('',(-1.,0.,0.));
#2842=AXIS2_PLACEMENT_3D('',#2839,#2840,#2841);
#2843=CYLINDRICAL_SURFACE('',#2842,4.4958);
#2844=ORIENTED_EDGE('',*,*,#1577,.T.);
#2845=DIRECTION('',(0.,0.,-1.));
#2846=VECTOR('',#2845,1.);
#2847=CARTESIAN_POINT('',(25.9860285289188,-19.1389,12.7));
#2848=LINE('',#2847,#2846);
#2849=EDGE_CURVE('E1465',#1265,#1567,#2848,.T.);
#2850=ORIENTED_EDGE('',*,*,#2849,.F.);
#2851=ORIENTED_EDGE('',*,*,#1266,.F.);
#2852=ORIENTED_EDGE('',*,*,#2832,.T.);
#2853=EDGE_LOOP('',(#2844,#2850,#2851,#2852));
#2854=FACE_BOUND('',#2853,.T.);
#2855=ADVANCED_FACE('F1258',(#2854),#2843,.T.);
#2856=CARTESIAN_POINT('',(22.1361,-19.1389,12.7));
#2857=DIRECTION('',(0.,-1.,0.));
#2858=DIRECTION('',(0.,0.,-1.));
#2859=AXIS2_PLACEMENT_3D('',#2856,#2857,#2858);
#2860=PLANE('',#2859);
#2861=ORIENTED_EDGE('',*,*,#1568,.T.);
#2862=DIRECTION('',(0.,0.,-1.));
#2863=VECTOR('',#2862,1.);
#2864=CARTESIAN_POINT('',(22.1361,-19.1389,12.7));
#2865=LINE('',#2864,#2863);
#2866=EDGE_CURVE('E1462',#1273,#1559,#2865,.T.);
#2867=ORIENTED_EDGE('',*,*,#2866,.F.);
#2868=ORIENTED_EDGE('',*,*,#1274,.F.);
#2869=ORIENTED_EDGE('',*,*,#2849,.T.);
#2870=EDGE_LOOP('',(#2861,#2867,#2868,#2869));
#2871=FACE_BOUND('',#2870,.T.);
#2872=ADVANCED_FACE('F1267',(#2871),#2860,.F.);
#2873=CARTESIAN_POINT('',(22.1361,19.1389,12.7));
#2874=DIRECTION('',(-1.,0.,0.));
#2875=DIRECTION('',(0.,0.,1.));
#2876=AXIS2_PLACEMENT_3D('',#2873,#2874,#2875);
#2877=PLANE('',#2876);
#2878=ORIENTED_EDGE('',*,*,#1560,.T.);
#2879=DIRECTION('',(0.,0.,-1.));
#2880=VECTOR('',#2879,1.);
#2881=CARTESIAN_POINT('',(22.1361,19.1389,12.7));
#2882=LINE('',#2881,#2880);
#2883=EDGE_CURVE('E1459',#1281,#1551,#2882,.T.);
#2884=ORIENTED_EDGE('',*,*,#2883,.F.);
#2885=ORIENTED_EDGE('',*,*,#1282,.F.);
#2886=ORIENTED_EDGE('',*,*,#2866,.T.);
#2887=EDGE_LOOP('',(#2878,#2884,#2885,#2886));
#2888=FACE_BOUND('',#2887,.T.);
#2889=ADVANCED_FACE('F1276',(#2888),#2877,.F.);
#2890=CARTESIAN_POINT('',(25.9860285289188,19.1389,12.7));
#2891=DIRECTION('',(0.,1.,0.));
#2892=DIRECTION('',(0.,0.,1.));
#2893=AXIS2_PLACEMENT_3D('',#2890,#2891,#2892);
#2894=PLANE('',#2893);
#2895=ORIENTED_EDGE('',*,*,#1552,.T.);
#2896=DIRECTION('',(0.,0.,-1.));
#2897=VECTOR('',#2896,1.);
#2898=CARTESIAN_POINT('',(25.9860285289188,19.1389,12.7));
#2899=LINE('',#2898,#2897);
#2900=EDGE_CURVE('E1351',#1289,#1543,#2899,.T.);
#2901=ORIENTED_EDGE('',*,*,#2900,.F.);
#2902=ORIENTED_EDGE('',*,*,#1290,.F.);
#2903=ORIENTED_EDGE('',*,*,#2883,.T.);
#2904=EDGE_LOOP('',(#2895,#2901,#2902,#2903));
#2905=FACE_BOUND('',#2904,.T.);
#2906=ADVANCED_FACE('F1285',(#2905),#2894,.F.);
#2907=CARTESIAN_POINT('',(29.337,22.1361,12.7));
#2908=DIRECTION('',(0.,0.,-1.));
#2909=DIRECTION('',(-1.,0.,0.));
#2910=AXIS2_PLACEMENT_3D('',#2907,#2908,#2909);
#2911=CYLINDRICAL_SURFACE('',#2910,4.4958);
#2912=ORIENTED_EDGE('',*,*,#1544,.T.);
#2913=ORIENTED_EDGE('',*,*,#2441,.F.);
#2914=ORIENTED_EDGE('',*,*,#1299,.F.);
#2915=ORIENTED_EDGE('',*,*,#2900,.T.);
#2916=EDGE_LOOP('',(#2912,#2913,#2914,#2915));
#2917=FACE_BOUND('',#2916,.T.);
#2918=ADVANCED_FACE('F1294',(#2917),#2911,.T.);
#2919=CLOSED_SHELL('',(#58,#89,#120,#151,#182,#215,#246,#279,#310,#343,#374,#407,#449,#491,#533,
#564,#597,#628,#659,#690,#721,#752,#785,#816,#847,#878,#902,#1421,#1940,#1962,#1979,#1996,#2013,
#2030,#2047,#2064,#2081,#2098,#2115,#2132,#2149,#2166,#2183,#2205,#2222,#2239,#2256,#2273,#2290,
#2307,#2324,#2341,#2358,#2375,#2392,#2404,#2416,#2423,#2445,#2462,#2479,#2496,#2513,#2530,#2547,
#2564,#2581,#2598,#2615,#2627,#2634,#2651,#2668,#2685,#2702,#2719,#2736,#2753,#2770,#2787,#2804,
#2821,#2838,#2855,#2872,#2889,#2906,#2918));
#2920=MANIFOLD_SOLID_BREP('B2',#2919);
#2921=ADVANCED_BREP_SHAPE_REPRESENTATION('',(#18,#2920),#14);
#2922=SHAPE_DEFINITION_REPRESENTATION(#9,#2921);
ENDSEC;
END-ISO-10303-21;
